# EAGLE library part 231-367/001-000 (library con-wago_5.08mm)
Serie 231, Stiftleiste (für Leiterplatten) Einlötstift gerade 1,2x1,2 mm / Series 231, Male header (for PCBs) Straight solder pin 1.2 x 1.2 mm Polzahl / Pole No.: 7 Rastermaß / Pitch: 5.08 mm Bemessungsspannung / Rated Voltage: 320 V Nennstrom / Nominal Current: 12 A Lötstiftlänge: / Solder Pin Length: 5 mm Farbe / Color: orange / orange Stand: 01.01.2012. Die jeweils aktuellen Daten zu diesem Artikel finden Sie in unserem Produktkatalog, den Sie unter www.wago.com einsehen können. As of: 01/01/2012. Please find the newest data for this article in our product catalogue, which can be viewed under www.wago.com.

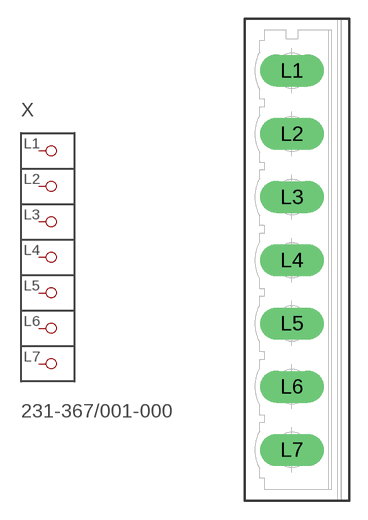
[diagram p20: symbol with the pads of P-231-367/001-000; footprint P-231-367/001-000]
Designator prefix X

## 231-367/001-000  [P-231-367/001-000]
L1  P1
L2  P2
L3  P3
L4  P4
L5  P5
L6  P6
L7  P7

## Footprint P-231-367/001-000 (pad centres in mm)
drill 1.7 long: L1 -0.4,15.2; L2 -0.4,10.12; L3 -0.4,5.04; L4 -0.4,-0.04; L5 -0.4,-5.12; L6 -0.4,-10.2; L7 -0.4,-15.28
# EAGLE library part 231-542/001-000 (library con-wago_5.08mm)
Serie 231, Stiftleiste mit abgewinkelten Einlötstiften / Series 231, Male connector with angled solder pins Polzahl / Pole No.: 12 Rastermaß / Pitch: 5.08 mm Bemessungsspannung / Rated Voltage: 320 V Nennstrom / Nominal Current: 16 A Lötstiftlänge: / Solder Pin Length: 3.8 mm Farbe / Color: orange / orange Stand: 01.01.2012. Die jeweils aktuellen Daten zu diesem Artikel finden Sie in unserem Produktkatalog, den Sie unter www.wago.com einsehen können. As of: 01/01/2012. Please find the newest data for this article in our product catalogue, which can be viewed under www.wago.com.

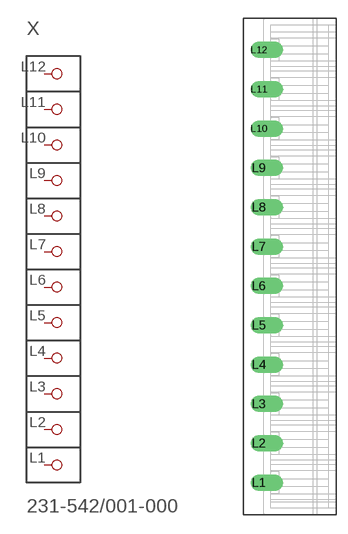
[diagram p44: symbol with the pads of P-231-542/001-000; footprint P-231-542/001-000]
Designator prefix X

## 231-542/001-000  [P-231-542/001-000]
L1  P1
L2  P2
L3  P3
L4  P4
L5  P5
L6  P6
L7  P7
L8  P8
L9  P9
L10  P10
L11  P11
L12  P12

## Footprint P-231-542/001-000 (pad centres in mm)
drill 1.4 offset: L1 -4,-27.9; L2 -4,-22.82; L3 -4,-17.74; L4 -4,-12.66; L5 -4,-7.58; L6 -4,-2.5; L7 -4,2.58; L8 -4,7.66; L9 -4,12.74; L10 -4,17.82; L11 -3.99,22.9; L12 -4,27.98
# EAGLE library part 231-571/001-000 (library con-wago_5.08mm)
Serie 231, Stiftleiste mit abgewinkelten Einlötstiften / Series 231, Male connector with angled solder pins Polzahl / Pole No.: 11 Rastermaß / Pitch: 5.08 mm Bemessungsspannung / Rated Voltage: 320 V Nennstrom / Nominal Current: 16 A Lötstiftlänge: / Solder Pin Length: 3.8 mm Farbe / Color: orange / orange Stand: 01.01.2012. Die jeweils aktuellen Daten zu diesem Artikel finden Sie in unserem Produktkatalog, den Sie unter www.wago.com einsehen können. As of: 01/01/2012. Please find the newest data for this article in our product catalogue, which can be viewed under www.wago.com.

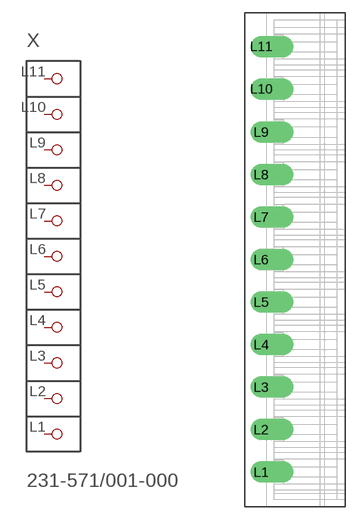
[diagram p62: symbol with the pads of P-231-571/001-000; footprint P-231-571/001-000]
Designator prefix X

## 231-571/001-000  [P-231-571/001-000]
L1  P1
L2  P2
L3  P3
L4  P4
L5  P5
L6  P6
L7  P7
L8  P8
L9  P9
L10  P10
L11  P11

## Footprint P-231-571/001-000 (pad centres in mm)
drill 1.7 offset: L1 -4,-25.36; L2 -4,-20.28; L3 -4,-15.2; L4 -4,-10.12; L5 -4,-5.04; L6 -4,0.04; L7 -4,5.12; L8 -4,10.2; L9 -4,15.28; L10 -3.99,20.36; L11 -4,25.44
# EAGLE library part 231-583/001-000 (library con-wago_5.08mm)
Serie 231, Stiftleiste mit abgewinkelten Einlötstiften / Series 231, Male connector with angled solder pins Polzahl / Pole No.: 23 Rastermaß / Pitch: 5.08 mm Bemessungsspannung / Rated Voltage: 320 V Nennstrom / Nominal Current: 16 A Lötstiftlänge: / Solder Pin Length: 3.8 mm Farbe / Color: orange / orange Stand: 01.01.2012. Die jeweils aktuellen Daten zu diesem Artikel finden Sie in unserem Produktkatalog, den Sie unter www.wago.com einsehen können. As of: 01/01/2012. Please find the newest data for this article in our product catalogue, which can be viewed under www.wago.com.

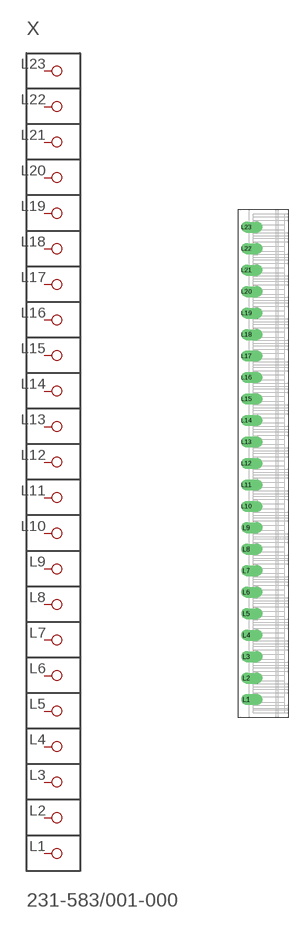
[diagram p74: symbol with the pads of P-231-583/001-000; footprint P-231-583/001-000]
Designator prefix X

## 231-583/001-000  [P-231-583/001-000]
L1  P1
L2  P2
L3  P3
L4  P4
L5  P5
L6  P6
L7  P7
L8  P8
L9  P9
L10  P10
L11  P11
L12  P12
L13  P13
L14  P14
L15  P15
L16  P16
L17  P17
L18  P18
L19  P19
L20  P20
L21  P21
L22  P22
L23  P23

## Footprint P-231-583/001-000 (pad centres in mm)
drill 1.7 offset: L1 -4,-55.84; L2 -4,-50.76; L3 -4,-45.68; L4 -4,-40.6; L5 -4,-35.52; L6 -4,-30.44; L7 -4,-25.36; L8 -4,-20.28; L9 -4,-15.2; L10 -4,-10.12; L11 -4,-5.04; L12 -4,0.04; L13 -4,5.12; L14 -4,10.2; L15 -4,15.28; L16 -4,20.36; L17 -4,25.44; L18 -4,30.52; L19 -4,35.6; L20 -4,40.68; L21 -4,45.76; L22 -3.99,50.84; L23 -4,55.92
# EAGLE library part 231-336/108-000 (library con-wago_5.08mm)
Serie 231, Stiftleiste mit geraden Einlötstiften / Series 231, Male connector with straight solder pins Polzahl / Pole No.: 6 Rastermaß / Pitch: 5.08 mm Bemessungsspannung / Rated Voltage: 320 V Nennstrom / Nominal Current: 12 A Lötstiftlänge: / Solder Pin Length: 5 mm Farbe / Color: orange / orange Stand: 01.01.2012. Die jeweils aktuellen Daten zu diesem Artikel finden Sie in unserem Produktkatalog, den Sie unter www.wago.com einsehen können. As of: 01/01/2012. Please find the newest data for this article in our product catalogue, which can be viewed under www.wago.com.

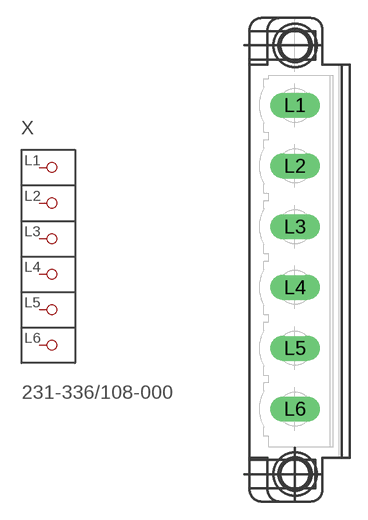
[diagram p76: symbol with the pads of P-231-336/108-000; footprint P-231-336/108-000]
Designator prefix X

## 231-336/108-000  [P-231-336/108-000]
L1  P1
L2  P2
L3  P3
L4  P4
L5  P5
L6  P6

## Footprint P-231-336/108-000 (pad centres in mm)
drill 1.4 long: L1 -0.192,12.925; L2 -0.192,7.845; L3 -0.192,2.765; L4 -0.192,-2.315; L5 -0.192,-7.395; L6 -0.192,-12.475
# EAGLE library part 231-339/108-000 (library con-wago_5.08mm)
Serie 231, Stiftleiste (für Leiterplatten) Einlötstift gerade 1 x 1 mm / Series 231, Male header (for PCBs) Straight solder pin 1 x 1 mm Polzahl / Pole No.: 9 Bemessungsspannung / Rated Voltage: 320 V Nennstrom / Nominal Current: 12 A Lötstiftlänge: / Solder Pin Length: 5 mm Farbe / Color: orange / orange Stand: 01.01.2012. Die jeweils aktuellen Daten zu diesem Artikel finden Sie in unserem Produktkatalog, den Sie unter www.wago.com einsehen können. As of: 01/01/2012. Please find the newest data for this article in our product catalogue, which can be viewed under www.wago.com.

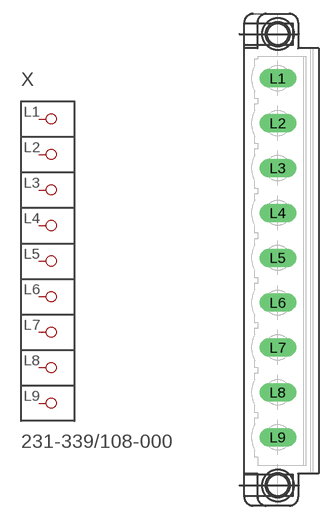
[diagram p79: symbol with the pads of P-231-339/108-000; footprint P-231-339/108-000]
Designator prefix X

## 231-339/108-000  [P-231-339/108-000]
L1  P1
L2  P2
L3  P3
L4  P4
L5  P5
L6  P6
L7  P7
L8  P8
L9  P9

## Footprint P-231-339/108-000 (pad centres in mm)
drill 1.4 long: L1 -0.117,20.545; L2 -0.117,15.465; L3 -0.117,10.385; L4 -0.117,5.305; L5 -0.117,0.225; L6 -0.117,-4.855; L7 -0.117,-9.935; L8 -0.117,-15.015; L9 -0.117,-20.095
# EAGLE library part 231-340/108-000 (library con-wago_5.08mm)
Serie 231, Stiftleiste (für Leiterplatten) Einlötstift gerade 1 x 1 mm / Series 231, Male header (for PCBs) Straight solder pin 1 x 1 mm Polzahl / Pole No.: 10 Bemessungsspannung / Rated Voltage: 320 V Nennstrom / Nominal Current: 12 A Lötstiftlänge: / Solder Pin Length: 5 mm Farbe / Color: orange / orange Stand: 01.01.2012. Die jeweils aktuellen Daten zu diesem Artikel finden Sie in unserem Produktkatalog, den Sie unter www.wago.com einsehen können. As of: 01/01/2012. Please find the newest data for this article in our product catalogue, which can be viewed under www.wago.com.

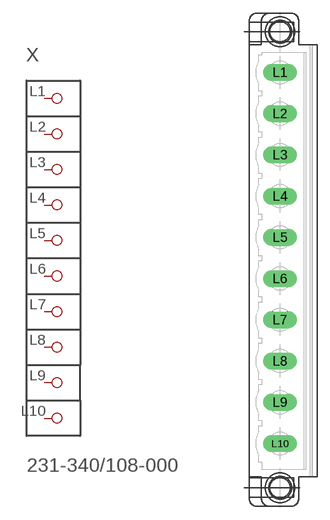
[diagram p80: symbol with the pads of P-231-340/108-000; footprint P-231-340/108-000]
Designator prefix X

## 231-340/108-000  [P-231-340/108-000]
L1  P1
L2  P2
L3  P3
L4  P4
L5  P5
L6  P6
L7  P7
L8  P8
L9  P9
L10  P10

## Footprint P-231-340/108-000 (pad centres in mm)
drill 1.4 long: L1 -0.092,23.085; L2 -0.092,18.005; L3 -0.092,12.925; L4 -0.092,7.845; L5 -0.092,2.765; L6 -0.092,-2.315; L7 -0.092,-7.395; L8 -0.092,-12.475; L9 -0.092,-17.555; L10 -0.092,-22.635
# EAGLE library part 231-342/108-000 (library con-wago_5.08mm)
Serie 231, Stiftleiste (für Leiterplatten) Einlötstift gerade 1 x 1 mm / Series 231, Male header (for PCBs) Straight solder pin 1 x 1 mm Polzahl / Pole No.: 12 Bemessungsspannung / Rated Voltage: 320 V Nennstrom / Nominal Current: 12 A Lötstiftlänge: / Solder Pin Length: 5 mm Farbe / Color: orange / orange Stand: 01.01.2012. Die jeweils aktuellen Daten zu diesem Artikel finden Sie in unserem Produktkatalog, den Sie unter www.wago.com einsehen können. As of: 01/01/2012. Please find the newest data for this article in our product catalogue, which can be viewed under www.wago.com.

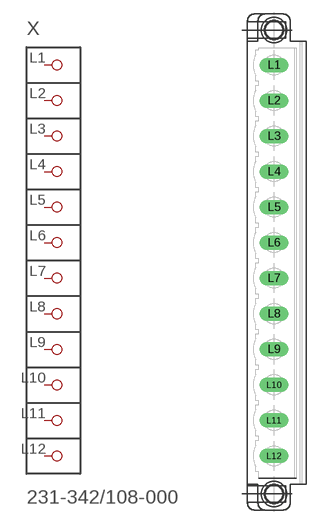
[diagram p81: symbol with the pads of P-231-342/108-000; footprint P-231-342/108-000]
Designator prefix X

## 231-342/108-000  [P-231-342/108-000]
L1  P1
L2  P2
L3  P3
L4  P4
L5  P5
L6  P6
L7  P7
L8  P8
L9  P9
L10  P10
L11  P11
L12  P12

## Footprint P-231-342/108-000 (pad centres in mm)
drill 1.4 long: L1 -0.042,28.165; L2 -0.042,23.085; L3 -0.042,18.005; L4 -0.042,12.925; L5 -0.042,7.845; L6 -0.042,2.765; L7 -0.042,-2.315; L8 -0.042,-7.395; L9 -0.042,-12.475; L10 -0.042,-17.555; L11 -0.042,-22.635; L12 -0.042,-27.715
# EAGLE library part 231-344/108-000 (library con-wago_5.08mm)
Serie 231, Stiftleiste mit geraden Einlötstiften / Series 231, Male connector with straight solder pins Polzahl / Pole No.: 14 Bemessungsspannung / Rated Voltage: 320 V Nennstrom / Nominal Current: 12 A Lötstiftlänge: / Solder Pin Length: 5 mm Farbe / Color: orange / orange Stand: 01.01.2012. Die jeweils aktuellen Daten zu diesem Artikel finden Sie in unserem Produktkatalog, den Sie unter www.wago.com einsehen können. As of: 01/01/2012. Please find the newest data for this article in our product catalogue, which can be viewed under www.wago.com.

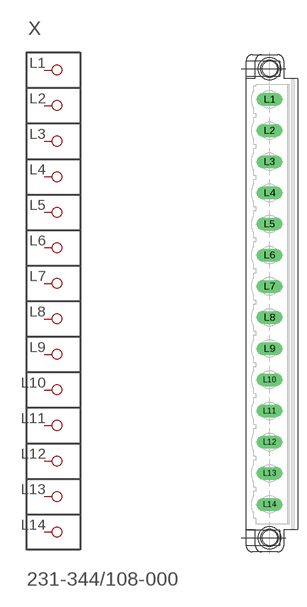
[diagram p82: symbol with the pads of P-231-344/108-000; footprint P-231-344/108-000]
Designator prefix X

## 231-344/108-000  [P-231-344/108-000]
L1  P1
L2  P2
L3  P3
L4  P4
L5  P5
L6  P6
L7  P7
L8  P8
L9  P9
L10  P10
L11  P11
L12  P12
L13  P13
L14  P14

## Footprint P-231-344/108-000 (pad centres in mm)
drill 1.4 long: L1 0.008,33.245; L2 0.008,28.165; L3 0.008,23.085; L4 0.008,18.005; L5 0.008,12.925; L6 0.008,7.845; L7 0.008,2.765; L8 0.008,-2.315; L9 0.008,-7.395; L10 0.008,-12.475; L11 0.008,-17.555; L12 0.008,-22.635; L13 0.008,-27.715; L14 0.008,-32.795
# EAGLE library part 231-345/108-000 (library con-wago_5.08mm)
Serie 231, Stiftleiste mit geraden Einlötstiften / Series 231, Male connector with straight solder pins Polzahl / Pole No.: 15 Rastermaß / Pitch: 5.08 mm Bemessungsspannung / Rated Voltage: 320 V Nennstrom / Nominal Current: 12 A Lötstiftlänge: / Solder Pin Length: 5 mm Farbe / Color: orange / orange Stand: 01.01.2012. Die jeweils aktuellen Daten zu diesem Artikel finden Sie in unserem Produktkatalog, den Sie unter www.wago.com einsehen können. As of: 01/01/2012. Please find the newest data for this article in our product catalogue, which can be viewed under www.wago.com.

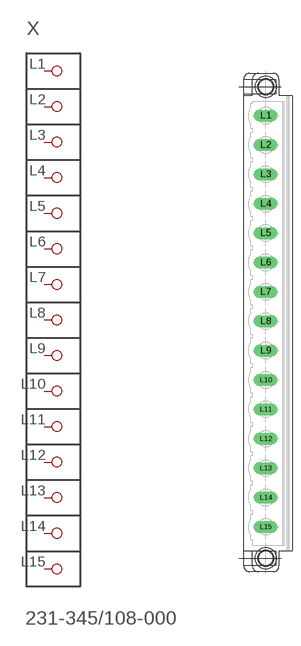
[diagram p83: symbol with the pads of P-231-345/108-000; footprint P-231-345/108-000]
Designator prefix X

## 231-345/108-000  [P-231-345/108-000]
L1  P1
L2  P2
L3  P3
L4  P4
L5  P5
L6  P6
L7  P7
L8  P8
L9  P9
L10  P10
L11  P11
L12  P12
L13  P13
L14  P14
L15  P15

## Footprint P-231-345/108-000 (pad centres in mm)
drill 1.4 long: L1 0.034,35.785; L2 0.034,30.705; L3 0.034,25.625; L4 0.034,20.545; L5 0.034,15.465; L6 0.034,10.385; L7 0.034,5.305; L8 0.034,0.225; L9 0.034,-4.855; L10 0.034,-9.935; L11 0.034,-15.015; L12 0.034,-20.095; L13 0.034,-25.175; L14 0.034,-30.255; L15 0.034,-35.335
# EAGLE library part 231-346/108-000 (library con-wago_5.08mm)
Serie 231, Stiftleiste mit geraden Einlötstiften / Series 231, Male connector with straight solder pins Polzahl / Pole No.: 16 Bemessungsspannung / Rated Voltage: 320 V Nennstrom / Nominal Current: 12 A Lötstiftlänge: / Solder Pin Length: 5 mm Farbe / Color: orange / orange Stand: 01.01.2012. Die jeweils aktuellen Daten zu diesem Artikel finden Sie in unserem Produktkatalog, den Sie unter www.wago.com einsehen können. As of: 01/01/2012. Please find the newest data for this article in our product catalogue, which can be viewed under www.wago.com.

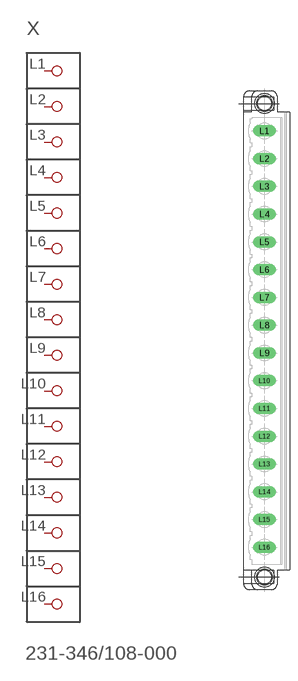
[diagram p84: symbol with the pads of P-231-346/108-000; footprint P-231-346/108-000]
Designator prefix X

## 231-346/108-000  [P-231-346/108-000]
L1  P1
L2  P2
L3  P3
L4  P4
L5  P5
L6  P6
L7  P7
L8  P8
L9  P9
L10  P10
L11  P11
L12  P12
L13  P13
L14  P14
L15  P15
L16  P16

## Footprint P-231-346/108-000 (pad centres in mm)
drill 1.4 long: L1 0.059,38.325; L2 0.059,33.245; L3 0.059,28.165; L4 0.059,23.085; L5 0.059,18.005; L6 0.059,12.925; L7 0.059,7.845; L8 0.059,2.765; L9 0.059,-2.315; L10 0.059,-7.395; L11 0.059,-12.475; L12 0.059,-17.555; L13 0.059,-22.635; L14 0.059,-27.715; L15 0.059,-32.795; L16 0.059,-37.875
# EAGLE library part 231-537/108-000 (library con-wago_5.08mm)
Serie 231, Stiftleiste mit abgewinkelten Einlötstiften / Series 231, Male connector with angled solder pins Polzahl / Pole No.: 7 Bemessungsspannung / Rated Voltage: 320 V Nennstrom / Nominal Current: 12 A Lötstiftlänge: / Solder Pin Length: 3.8 mm Farbe / Color: orange / orange Stand: 01.01.2012. Die jeweils aktuellen Daten zu diesem Artikel finden Sie in unserem Produktkatalog, den Sie unter www.wago.com einsehen können. As of: 01/01/2012. Please find the newest data for this article in our product catalogue, which can be viewed under www.wago.com.

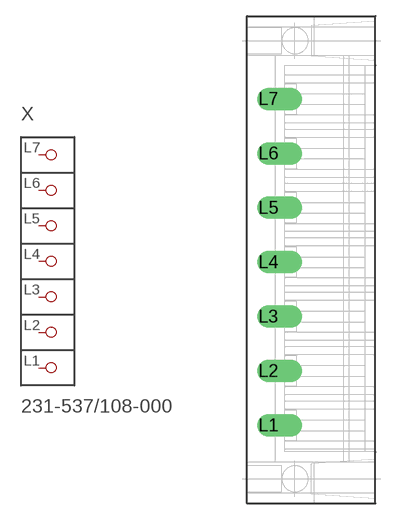
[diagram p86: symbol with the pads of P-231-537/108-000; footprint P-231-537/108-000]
Designator prefix X

## 231-537/108-000  [P-231-537/108-000]
L1  P1
L2  P2
L3  P3
L4  P4
L5  P5
L6  P6
L7  P7

## Footprint P-231-537/108-000 (pad centres in mm)
drill 1.4 offset: L1 -4,-15.465; L2 -4,-10.385; L3 -4,-5.305; L4 -4,-0.225; L5 -4,4.855; L6 -4,9.935; L7 -4,15.025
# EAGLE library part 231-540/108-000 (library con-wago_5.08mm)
Serie 231, Stiftleiste mit abgewinkelten Einlötstiften / Series 231, Male connector with angled solder pins Polzahl / Pole No.: 10 Bemessungsspannung / Rated Voltage: 320 V Nennstrom / Nominal Current: 12 A Lötstiftlänge: / Solder Pin Length: 3.8 mm Farbe / Color: orange / orange Stand: 01.01.2012. Die jeweils aktuellen Daten zu diesem Artikel finden Sie in unserem Produktkatalog, den Sie unter www.wago.com einsehen können. As of: 01/01/2012. Please find the newest data for this article in our product catalogue, which can be viewed under www.wago.com.

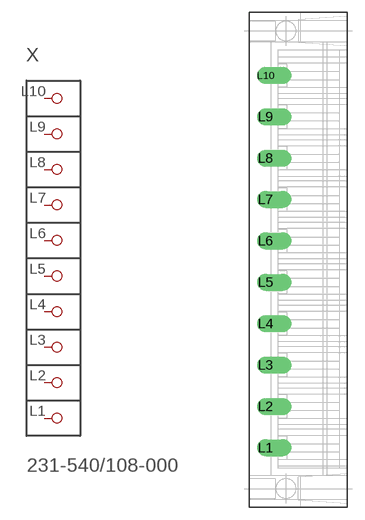
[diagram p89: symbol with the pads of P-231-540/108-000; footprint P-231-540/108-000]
Designator prefix X

## 231-540/108-000  [P-231-540/108-000]
L1  P1
L2  P2
L3  P3
L4  P4
L5  P5
L6  P6
L7  P7
L8  P8
L9  P9
L10  P10

## Footprint P-231-540/108-000 (pad centres in mm)
drill 1.4 offset: L1 -4,-23.085; L2 -4,-18.005; L3 -4,-12.925; L4 -4,-7.845; L5 -4,-2.765; L6 -4,2.315; L7 -4,7.395; L8 -4,12.475; L9 -4,17.555; L10 -4,22.645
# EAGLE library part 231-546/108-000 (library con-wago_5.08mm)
Serie 231, Stiftleiste (für Leiterplatten) Einlötstift abgewinkelt 1 x 1 mm / Series 231, Male header (for PCBs) Angled solder pin 1 x 1 mm Polzahl / Pole No.: 16 Bemessungsspannung / Rated Voltage: 320 V Nennstrom / Nominal Current: 12 A Lötstiftlänge: / Solder Pin Length: 3.8 mm Farbe / Color: orange / orange Stand: 01.01.2012. Die jeweils aktuellen Daten zu diesem Artikel finden Sie in unserem Produktkatalog, den Sie unter www.wago.com einsehen können. As of: 01/01/2012. Please find the newest data for this article in our product catalogue, which can be viewed under www.wago.com.

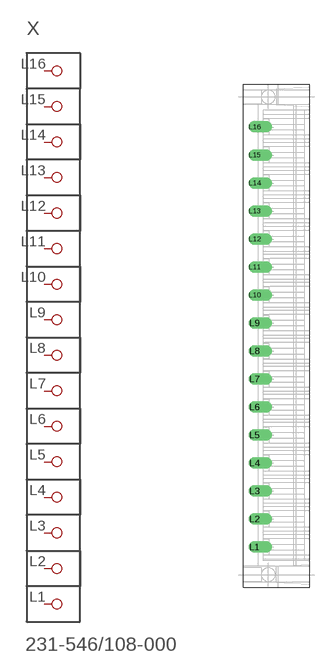
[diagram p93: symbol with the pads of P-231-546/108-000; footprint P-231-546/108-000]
Designator prefix X

## 231-546/108-000  [P-231-546/108-000]
L1  P1
L2  P2
L3  P3
L4  P4
L5  P5
L6  P6
L7  P7
L8  P8
L9  P9
L10  P10
L11  P11
L12  P12
L13  P13
L14  P14
L15  P15
L16  P16

## Footprint P-231-546/108-000 (pad centres in mm)
drill 1.4 offset: L1 -4,-38.325; L2 -4,-33.245; L3 -4,-28.165; L4 -4,-23.085; L5 -4,-18.005; L6 -4,-12.925; L7 -4,-7.845; L8 -4,-2.765; L9 -4,2.315; L10 -4,7.395; L11 -4,12.475; L12 -4,17.555; L13 -4,22.635; L14 -4,27.715; L15 -4,32.795; L16 -4,37.885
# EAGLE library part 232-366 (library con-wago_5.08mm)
Serie 232, Aufstock-Stiftleisten mit abgewinkelten Einlötstiften / Series 232, Male headers for double-deck assembly with angled solder pins Polzahl / Pole No.: 6 Rastermaß / Pitch: 5.08 mm Bemessungsspannung / Rated Voltage: 320 V Nennstrom / Nominal Current: 12 A Lötstiftlänge: / Solder Pin Length: 5 mm Farbe / Color: orange / orange Stand: 01.01.2012. Die jeweils aktuellen Daten zu diesem Artikel finden Sie in unserem Produktkatalog, den Sie unter www.wago.com einsehen können. As of: 01/01/2012. Please find the newest data for this article in our product catalogue, which can be viewed under www.wago.com.

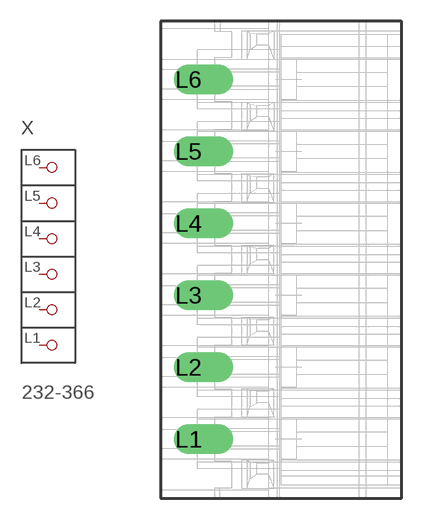
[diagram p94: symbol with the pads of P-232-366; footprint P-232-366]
Designator prefix X

## 232-366  [P-232-366]
L1  P1
L2  P2
L3  P3
L4  P4
L5  P5
L6  P6

## Footprint P-232-366 (pad centres in mm)
drill 1.4 offset: L1 -6.52,-12.66; L2 -6.52,-7.58; L3 -6.52,-2.5; L4 -6.52,2.58; L5 -6.52,7.66; L6 -6.52,12.74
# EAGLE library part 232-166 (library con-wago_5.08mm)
Serie 232, Federleiste mit geraden Einlötstiften / Series 232, Female connector with straight solder pins Polzahl / Pole No.: 6 Rastermaß / Pitch: 5.08 mm Bemessungsspannung / Rated Voltage: 160 V Nennstrom / Nominal Current: 6 A Lötstiftlänge: / Solder Pin Length: 5 mm Farbe / Color: orange / orange Stand: 01.01.2012. Die jeweils aktuellen Daten zu diesem Artikel finden Sie in unserem Produktkatalog, den Sie unter www.wago.com einsehen können. As of: 01/01/2012. Please find the newest data for this article in our product catalogue, which can be viewed under www.wago.com.

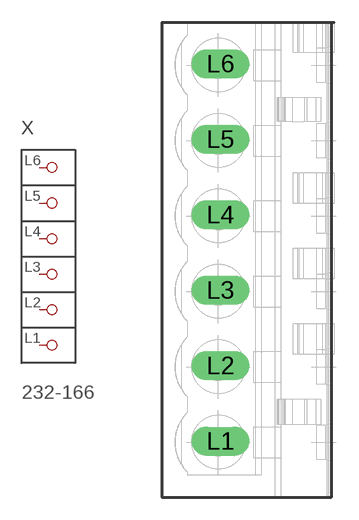
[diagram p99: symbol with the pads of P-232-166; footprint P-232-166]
Designator prefix X

## 232-166  [P-232-166]
L1  P1
L2  P2
L3  P3
L4  P4
L5  P5
L6  P6

## Footprint P-232-166 (pad centres in mm)
drill 1.3 long: L1 -1.926,-12.21; L2 -1.926,-7.13; L3 -1.926,-2.05; L4 -1.926,3.03; L5 -1.926,8.11; L6 -1.926,13.19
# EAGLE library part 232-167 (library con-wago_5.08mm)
Serie 232, Federleiste mit geraden Einlötstiften / Series 232, Female connector with straight solder pins Polzahl / Pole No.: 7 Rastermaß / Pitch: 5.08 mm Bemessungsspannung / Rated Voltage: 160 V Nennstrom / Nominal Current: 6 A Lötstiftlänge: / Solder Pin Length: 5 mm Farbe / Color: orange / orange Stand: 01.01.2012. Die jeweils aktuellen Daten zu diesem Artikel finden Sie in unserem Produktkatalog, den Sie unter www.wago.com einsehen können. As of: 01/01/2012. Please find the newest data for this article in our product catalogue, which can be viewed under www.wago.com.

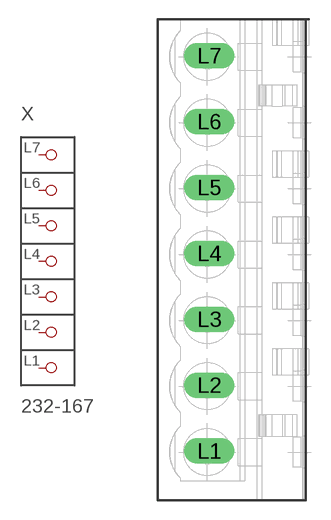
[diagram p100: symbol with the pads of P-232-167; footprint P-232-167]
Designator prefix X

## 232-167  [P-232-167]
L1  P1
L2  P2
L3  P3
L4  P4
L5  P5
L6  P6
L7  P7

## Footprint P-232-167 (pad centres in mm)
drill 1.3 long: L1 -1.95,-14.75; L2 -1.95,-9.67; L3 -1.95,-4.59; L4 -1.95,0.49; L5 -1.95,5.57; L6 -1.95,10.65; L7 -1.95,15.73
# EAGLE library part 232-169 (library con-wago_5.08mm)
Serie 232, Federleiste mit geraden Einlötstiften / Series 232, Female connector with straight solder pins Polzahl / Pole No.: 9 Rastermaß / Pitch: 5.08 mm Bemessungsspannung / Rated Voltage: 160 V Nennstrom / Nominal Current: 6 A Lötstiftlänge: / Solder Pin Length: 5 mm Farbe / Color: orange / orange Stand: 01.01.2012. Die jeweils aktuellen Daten zu diesem Artikel finden Sie in unserem Produktkatalog, den Sie unter www.wago.com einsehen können. As of: 01/01/2012. Please find the newest data for this article in our product catalogue, which can be viewed under www.wago.com.

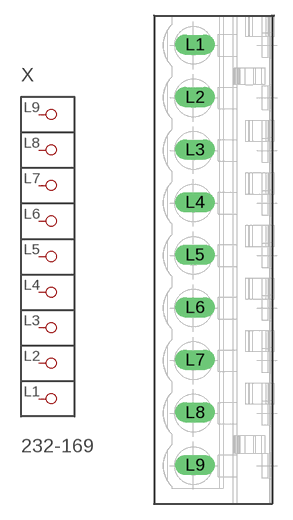
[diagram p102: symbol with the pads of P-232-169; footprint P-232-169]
Designator prefix X

## 232-169  [P-232-169]
L1  P1
L2  P2
L3  P3
L4  P4
L5  P5
L6  P6
L7  P7
L8  P8
L9  P9

## Footprint P-232-169 (pad centres in mm)
drill 1.3 long: L1 -1.998,20.81; L2 -1.998,15.73; L3 -1.998,10.65; L4 -1.998,5.57; L5 -1.998,0.49; L6 -1.998,-4.59; L7 -1.998,-9.67; L8 -1.998,-14.75; L9 -1.998,-19.83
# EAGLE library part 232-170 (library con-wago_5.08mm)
Serie 232, Federleiste mit geraden Einlötstiften / Series 232, Female connector with straight solder pins Polzahl / Pole No.: 10 Rastermaß / Pitch: 5.08 mm Bemessungsspannung / Rated Voltage: 160 V Nennstrom / Nominal Current: 6 A Lötstiftlänge: / Solder Pin Length: 5 mm Farbe / Color: orange / orange Stand: 01.01.2012. Die jeweils aktuellen Daten zu diesem Artikel finden Sie in unserem Produktkatalog, den Sie unter www.wago.com einsehen können. As of: 01/01/2012. Please find the newest data for this article in our product catalogue, which can be viewed under www.wago.com.

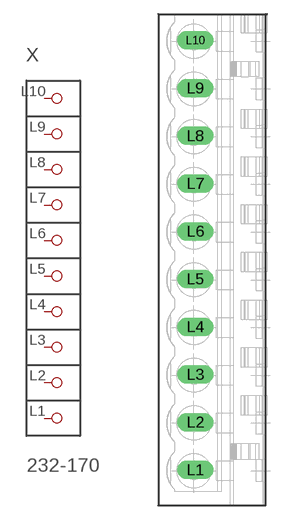
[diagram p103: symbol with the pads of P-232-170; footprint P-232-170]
Designator prefix X

## 232-170  [P-232-170]
L1  P1
L2  P2
L3  P3
L4  P4
L5  P5
L6  P6
L7  P7
L8  P8
L9  P9
L10  P10

## Footprint P-232-170 (pad centres in mm)
drill 1.3 long: L1 -2.023,-22.37; L2 -2.023,-17.29; L3 -2.023,-12.21; L4 -2.023,-7.13; L5 -2.023,-2.05; L6 -2.023,3.03; L7 -2.023,8.11; L8 -2.023,13.19; L9 -2.023,18.27; L10 -2.023,23.35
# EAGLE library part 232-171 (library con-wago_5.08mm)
Serie 232, Federleiste mit geraden Einlötstiften / Series 232, Female connector with straight solder pins Polzahl / Pole No.: 11 Rastermaß / Pitch: 5.08 mm Bemessungsspannung / Rated Voltage: 160 V Nennstrom / Nominal Current: 6 A Lötstiftlänge: / Solder Pin Length: 5 mm Farbe / Color: orange / orange Stand: 01.01.2012. Die jeweils aktuellen Daten zu diesem Artikel finden Sie in unserem Produktkatalog, den Sie unter www.wago.com einsehen können. As of: 01/01/2012. Please find the newest data for this article in our product catalogue, which can be viewed under www.wago.com.

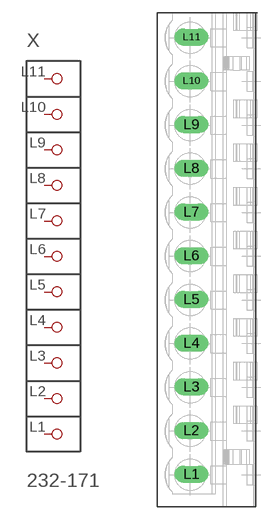
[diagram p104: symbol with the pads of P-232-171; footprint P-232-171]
Designator prefix X

## 232-171  [P-232-171]
L1  P1
L2  P2
L3  P3
L4  P4
L5  P5
L6  P6
L7  P7
L8  P8
L9  P9
L10  P10
L11  P11

## Footprint P-232-171 (pad centres in mm)
drill 1.3 long: L1 -2.048,-24.91; L2 -2.048,-19.83; L3 -2.048,-14.75; L4 -2.048,-9.67; L5 -2.048,-4.59; L6 -2.048,0.49; L7 -2.048,5.57; L8 -2.048,10.65; L9 -2.048,15.73; L10 -2.048,20.81; L11 -2.048,25.89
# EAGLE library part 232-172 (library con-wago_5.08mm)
Serie 232, Federleiste mit geraden Einlötstiften / Series 232, Female connector with straight solder pins Polzahl / Pole No.: 12 Rastermaß / Pitch: 5.08 mm Bemessungsspannung / Rated Voltage: 160 V Nennstrom / Nominal Current: 6 A Lötstiftlänge: / Solder Pin Length: 5 mm Farbe / Color: orange / orange Stand: 01.01.2012. Die jeweils aktuellen Daten zu diesem Artikel finden Sie in unserem Produktkatalog, den Sie unter www.wago.com einsehen können. As of: 01/01/2012. Please find the newest data for this article in our product catalogue, which can be viewed under www.wago.com.

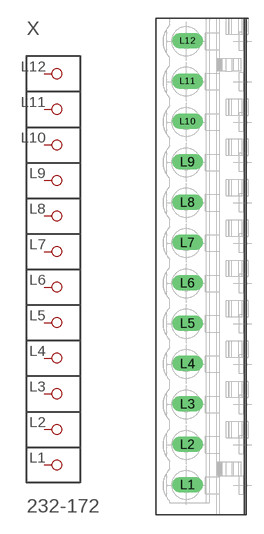
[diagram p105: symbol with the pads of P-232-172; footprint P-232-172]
Designator prefix X

## 232-172  [P-232-172]
L1  P1
L2  P2
L3  P3
L4  P4
L5  P5
L6  P6
L7  P7
L8  P8
L9  P9
L10  P10
L11  P11
L12  P12

## Footprint P-232-172 (pad centres in mm)
drill 1.3 long: L1 -2.072,-27.45; L2 -2.072,-22.37; L3 -2.072,-17.29; L4 -2.072,-12.21; L5 -2.072,-7.13; L6 -2.072,-2.05; L7 -2.072,3.03; L8 -2.072,8.11; L9 -2.072,13.19; L10 -2.072,18.27; L11 -2.072,23.35; L12 -2.072,28.43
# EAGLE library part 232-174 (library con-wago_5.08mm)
Serie 232, Federleiste mit geraden Einlötstiften / Series 232, Female connector with straight solder pins Polzahl / Pole No.: 14 Rastermaß / Pitch: 5.08 mm Bemessungsspannung / Rated Voltage: 160 V Nennstrom / Nominal Current: 6 A Lötstiftlänge: / Solder Pin Length: 5 mm Farbe / Color: orange / orange Stand: 01.01.2012. Die jeweils aktuellen Daten zu diesem Artikel finden Sie in unserem Produktkatalog, den Sie unter www.wago.com einsehen können. As of: 01/01/2012. Please find the newest data for this article in our product catalogue, which can be viewed under www.wago.com.

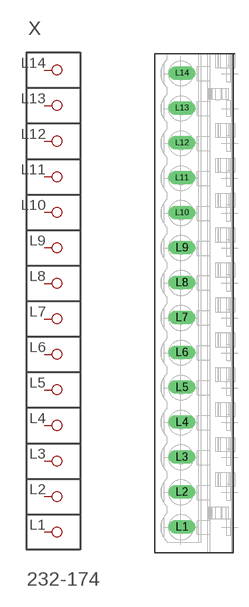
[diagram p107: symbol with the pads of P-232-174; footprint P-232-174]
Designator prefix X

## 232-174  [P-232-174]
L1  P1
L2  P2
L3  P3
L4  P4
L5  P5
L6  P6
L7  P7
L8  P8
L9  P9
L10  P10
L11  P11
L12  P12
L13  P13
L14  P14

## Footprint P-232-174 (pad centres in mm)
drill 1.3 long: L1 -2.123,-32.53; L2 -2.123,-27.45; L3 -2.123,-22.37; L4 -2.123,-17.29; L5 -2.123,-12.21; L6 -2.123,-7.13; L7 -2.123,-2.05; L8 -2.123,3.03; L9 -2.123,8.11; L10 -2.123,13.19; L11 -2.123,18.27; L12 -2.123,23.35; L13 -2.123,28.43; L14 -2.123,33.51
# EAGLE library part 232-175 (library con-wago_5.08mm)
Serie 232, Federleiste mit geraden Einlötstiften / Series 232, Female connector with straight solder pins Polzahl / Pole No.: 15 Rastermaß / Pitch: 5.08 mm Bemessungsspannung / Rated Voltage: 160 V Nennstrom / Nominal Current: 6 A Lötstiftlänge: / Solder Pin Length: 5 mm Farbe / Color: orange / orange Stand: 01.01.2012. Die jeweils aktuellen Daten zu diesem Artikel finden Sie in unserem Produktkatalog, den Sie unter www.wago.com einsehen können. As of: 01/01/2012. Please find the newest data for this article in our product catalogue, which can be viewed under www.wago.com.

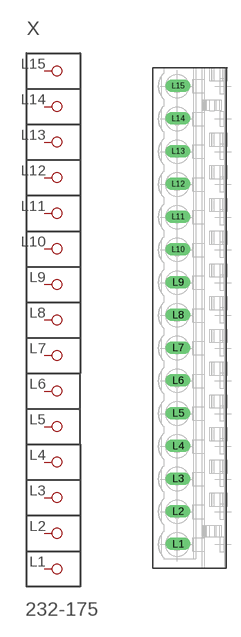
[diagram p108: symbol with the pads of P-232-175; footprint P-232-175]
Designator prefix X

## 232-175  [P-232-175]
L1  P1
L2  P2
L3  P3
L4  P4
L5  P5
L6  P6
L7  P7
L8  P8
L9  P9
L10  P10
L11  P11
L12  P12
L13  P13
L14  P14
L15  P15

## Footprint P-232-175 (pad centres in mm)
drill 1.3 long: L1 -2.147,-35.07; L2 -2.147,-29.99; L3 -2.147,-24.91; L4 -2.147,-19.83; L5 -2.147,-14.75; L6 -2.147,-9.67; L7 -2.147,-4.59; L8 -2.147,0.49; L9 -2.147,5.57; L10 -2.147,10.65; L11 -2.147,15.73; L12 -2.147,20.81; L13 -2.147,25.89; L14 -2.147,30.97; L15 -2.147,36.05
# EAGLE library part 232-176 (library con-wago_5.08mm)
Serie 232, Federleiste mit geraden Einlötstiften / Series 232, Female connector with straight solder pins Polzahl / Pole No.: 16 Rastermaß / Pitch: 5.08 mm Bemessungsspannung / Rated Voltage: 160 V Nennstrom / Nominal Current: 6 A Lötstiftlänge: / Solder Pin Length: 5 mm Farbe / Color: orange / orange Stand: 01.01.2012. Die jeweils aktuellen Daten zu diesem Artikel finden Sie in unserem Produktkatalog, den Sie unter www.wago.com einsehen können. As of: 01/01/2012. Please find the newest data for this article in our product catalogue, which can be viewed under www.wago.com.

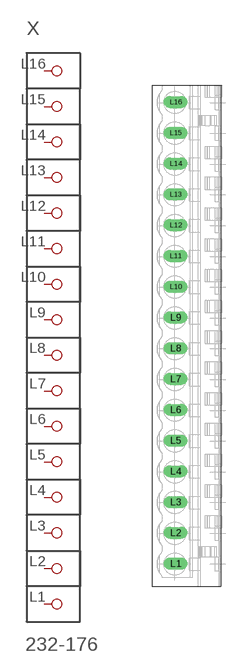
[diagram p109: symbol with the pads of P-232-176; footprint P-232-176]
Designator prefix X

## 232-176  [P-232-176]
L1  P1
L2  P2
L3  P3
L4  P4
L5  P5
L6  P6
L7  P7
L8  P8
L9  P9
L10  P10
L11  P11
L12  P12
L13  P13
L14  P14
L15  P15
L16  P16

## Footprint P-232-176 (pad centres in mm)
drill 1.3 long: L1 -2.173,-37.61; L2 -2.173,-32.53; L3 -2.173,-27.45; L4 -2.173,-22.37; L5 -2.173,-17.29; L6 -2.173,-12.21; L7 -2.173,-7.13; L8 -2.173,-2.05; L9 -2.173,3.03; L10 -2.173,8.11; L11 -2.173,13.19; L12 -2.173,18.27; L13 -2.173,23.35; L14 -2.173,28.43; L15 -2.173,33.51; L16 -2.173,38.59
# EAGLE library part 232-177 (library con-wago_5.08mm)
Serie 232, Federleiste mit geraden Einlötstiften / Series 232, Female connector with straight solder pins Polzahl / Pole No.: 17 Rastermaß / Pitch: 5.08 mm Bemessungsspannung / Rated Voltage: 160 V Nennstrom / Nominal Current: 6 A Lötstiftlänge: / Solder Pin Length: 5 mm Farbe / Color: orange / orange Stand: 01.01.2012. Die jeweils aktuellen Daten zu diesem Artikel finden Sie in unserem Produktkatalog, den Sie unter www.wago.com einsehen können. As of: 01/01/2012. Please find the newest data for this article in our product catalogue, which can be viewed under www.wago.com.

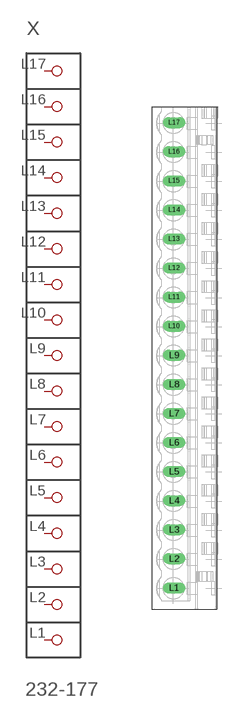
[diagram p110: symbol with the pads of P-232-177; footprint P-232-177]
Designator prefix X

## 232-177  [P-232-177]
L1  P1
L2  P2
L3  P3
L4  P4
L5  P5
L6  P6
L7  P7
L8  P8
L9  P9
L10  P10
L11  P11
L12  P12
L13  P13
L14  P14
L15  P15
L16  P16
L17  P17

## Footprint P-232-177 (pad centres in mm)
drill 1.3 long: L1 -2.198,-40.15; L2 -2.198,-35.07; L3 -2.198,-29.99; L4 -2.198,-24.91; L5 -2.198,-19.83; L6 -2.198,-14.75; L7 -2.198,-9.67; L8 -2.198,-4.59; L9 -2.198,0.49; L10 -2.198,5.57; L11 -2.198,10.65; L12 -2.198,15.73; L13 -2.198,20.81; L14 -2.198,25.89; L15 -2.198,30.97; L16 -2.198,36.05; L17 -2.198,41.13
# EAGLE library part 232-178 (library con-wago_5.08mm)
Serie 232, Federleiste mit geraden Einlötstiften / Series 232, Female connector with straight solder pins Polzahl / Pole No.: 18 Rastermaß / Pitch: 5.08 mm Bemessungsspannung / Rated Voltage: 160 V Nennstrom / Nominal Current: 6 A Lötstiftlänge: / Solder Pin Length: 5 mm Farbe / Color: orange / orange Stand: 01.01.2012. Die jeweils aktuellen Daten zu diesem Artikel finden Sie in unserem Produktkatalog, den Sie unter www.wago.com einsehen können. As of: 01/01/2012. Please find the newest data for this article in our product catalogue, which can be viewed under www.wago.com.

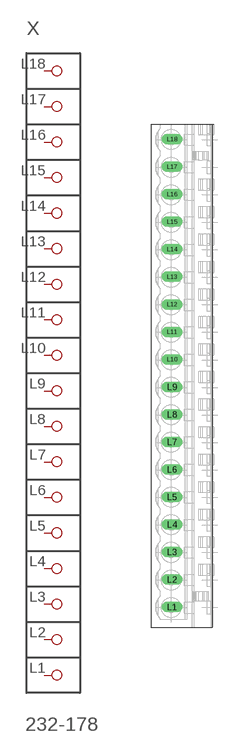
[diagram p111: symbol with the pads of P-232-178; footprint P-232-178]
Designator prefix X

## 232-178  [P-232-178]
L1  P1
L2  P2
L3  P3
L4  P4
L5  P5
L6  P6
L7  P7
L8  P8
L9  P9
L10  P10
L11  P11
L12  P12
L13  P13
L14  P14
L15  P15
L16  P16
L17  P17
L18  P18

## Footprint P-232-178 (pad centres in mm)
drill 1.3 long: L1 -2.223,-42.69; L2 -2.223,-37.61; L3 -2.223,-32.53; L4 -2.223,-27.45; L5 -2.223,-22.37; L6 -2.223,-17.29; L7 -2.223,-12.21; L8 -2.223,-7.13; L9 -2.223,-2.05; L10 -2.223,3.03; L11 -2.223,8.11; L12 -2.223,13.19; L13 -2.223,18.27; L14 -2.223,23.35; L15 -2.223,28.43; L16 -2.223,33.51; L17 -2.223,38.59; L18 -2.223,43.67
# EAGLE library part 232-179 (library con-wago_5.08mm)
Serie 232, Federleiste mit geraden Einlötstiften / Series 232, Female connector with straight solder pins Polzahl / Pole No.: 19 Rastermaß / Pitch: 5.08 mm Bemessungsspannung / Rated Voltage: 160 V Nennstrom / Nominal Current: 6 A Lötstiftlänge: / Solder Pin Length: 5 mm Farbe / Color: orange / orange Stand: 01.01.2012. Die jeweils aktuellen Daten zu diesem Artikel finden Sie in unserem Produktkatalog, den Sie unter www.wago.com einsehen können. As of: 01/01/2012. Please find the newest data for this article in our product catalogue, which can be viewed under www.wago.com.

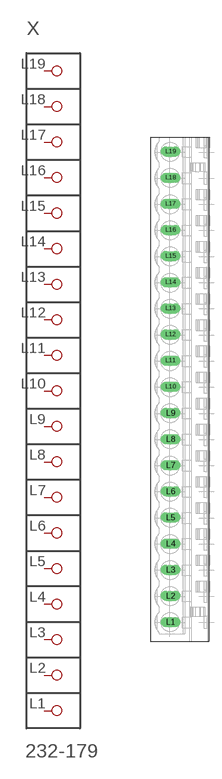
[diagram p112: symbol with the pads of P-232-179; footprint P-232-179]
Designator prefix X

## 232-179  [P-232-179]
L1  P1
L2  P2
L3  P3
L4  P4
L5  P5
L6  P6
L7  P7
L8  P8
L9  P9
L10  P10
L11  P11
L12  P12
L13  P13
L14  P14
L15  P15
L16  P16
L17  P17
L18  P18
L19  P19

## Footprint P-232-179 (pad centres in mm)
drill 1.3 long: L1 -2.248,-45.23; L2 -2.248,-40.15; L3 -2.248,-35.07; L4 -2.248,-29.99; L5 -2.248,-24.91; L6 -2.248,-19.83; L7 -2.248,-14.75; L8 -2.248,-9.67; L9 -2.248,-4.59; L10 -2.248,0.49; L11 -2.248,5.57; L12 -2.248,10.65; L13 -2.248,15.73; L14 -2.248,20.81; L15 -2.248,25.89; L16 -2.248,30.97; L17 -2.248,36.05; L18 -2.248,41.13; L19 -2.248,46.21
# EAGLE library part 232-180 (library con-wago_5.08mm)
Serie 232, Federleiste mit geraden Einlötstiften / Series 232, Female connector with straight solder pins Polzahl / Pole No.: 20 Rastermaß / Pitch: 5.08 mm Bemessungsspannung / Rated Voltage: 160 V Nennstrom / Nominal Current: 6 A Lötstiftlänge: / Solder Pin Length: 5 mm Farbe / Color: orange / orange Stand: 01.01.2012. Die jeweils aktuellen Daten zu diesem Artikel finden Sie in unserem Produktkatalog, den Sie unter www.wago.com einsehen können. As of: 01/01/2012. Please find the newest data for this article in our product catalogue, which can be viewed under www.wago.com.

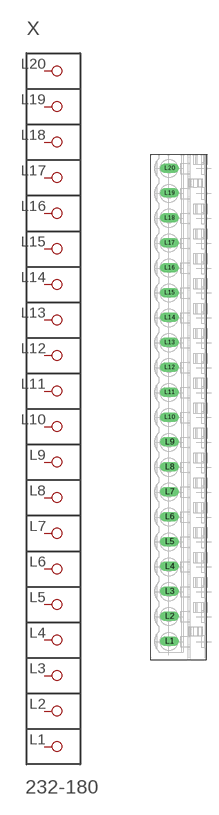
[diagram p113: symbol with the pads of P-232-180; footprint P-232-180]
Designator prefix X

## 232-180  [P-232-180]
L1  P1
L2  P2
L3  P3
L4  P4
L5  P5
L6  P6
L7  P7
L8  P8
L9  P9
L10  P10
L11  P11
L12  P12
L13  P13
L14  P14
L15  P15
L16  P16
L17  P17
L18  P18
L19  P19
L20  P20

## Footprint P-232-180 (pad centres in mm)
drill 1.3 long: L1 -2.273,-47.77; L2 -2.273,-42.69; L3 -2.273,-37.61; L4 -2.273,-32.53; L5 -2.273,-27.45; L6 -2.273,-22.37; L7 -2.273,-17.29; L8 -2.273,-12.21; L9 -2.273,-7.13; L10 -2.273,-2.05; L11 -2.273,3.03; L12 -2.273,8.11; L13 -2.273,13.19; L14 -2.273,18.27; L15 -2.273,23.35; L16 -2.273,28.43; L17 -2.273,33.51; L18 -2.273,38.59; L19 -2.273,43.67; L20 -2.273,48.75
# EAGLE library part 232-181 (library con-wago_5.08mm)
Serie 232, Federleiste mit geraden Einlötstiften / Series 232, Female connector with straight solder pins Polzahl / Pole No.: 21 Rastermaß / Pitch: 5.08 mm Bemessungsspannung / Rated Voltage: 160 V Nennstrom / Nominal Current: 6 A Lötstiftlänge: / Solder Pin Length: 5 mm Farbe / Color: orange / orange Stand: 01.01.2012. Die jeweils aktuellen Daten zu diesem Artikel finden Sie in unserem Produktkatalog, den Sie unter www.wago.com einsehen können. As of: 01/01/2012. Please find the newest data for this article in our product catalogue, which can be viewed under www.wago.com.

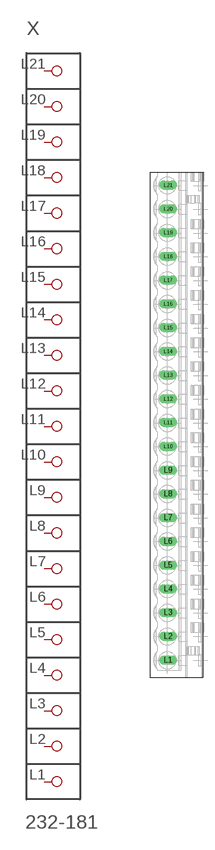
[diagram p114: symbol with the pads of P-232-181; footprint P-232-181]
Designator prefix X

## 232-181  [P-232-181]
L1  P1
L2  P2
L3  P3
L4  P4
L5  P5
L6  P6
L7  P7
L8  P8
L9  P9
L10  P10
L11  P11
L12  P12
L13  P13
L14  P14
L15  P15
L16  P16
L17  P17
L18  P18
L19  P19
L20  P20
L21  P21

## Footprint P-232-181 (pad centres in mm)
drill 1.3 long: L1 -2.299,-50.319; L2 -2.299,-45.239; L3 -2.299,-40.159; L4 -2.299,-35.079; L5 -2.299,-29.999; L6 -2.299,-24.919; L7 -2.299,-19.839; L8 -2.299,-14.759; L9 -2.299,-9.679; L10 -2.299,-4.599; L11 -2.299,0.481; L12 -2.299,5.561; L13 -2.299,10.641; L14 -2.299,15.721; L15 -2.299,20.801; L16 -2.299,25.881; L17 -2.299,30.961; L18 -2.299,36.041; L19 -2.299,41.121; L20 -2.299,46.201; L21 -2.299,51.281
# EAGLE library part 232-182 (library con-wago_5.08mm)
Serie 232, Federleiste mit geraden Einlötstiften / Series 232, Female connector with straight solder pins Polzahl / Pole No.: 22 Rastermaß / Pitch: 5.08 mm Bemessungsspannung / Rated Voltage: 160 V Nennstrom / Nominal Current: 6 A Lötstiftlänge: / Solder Pin Length: 5 mm Farbe / Color: orange / orange Stand: 01.01.2012. Die jeweils aktuellen Daten zu diesem Artikel finden Sie in unserem Produktkatalog, den Sie unter www.wago.com einsehen können. As of: 01/01/2012. Please find the newest data for this article in our product catalogue, which can be viewed under www.wago.com.

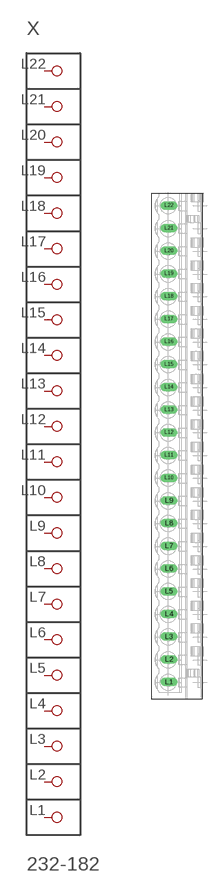
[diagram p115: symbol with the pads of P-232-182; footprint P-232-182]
Designator prefix X

## 232-182  [P-232-182]
L1  P1
L2  P2
L3  P3
L4  P4
L5  P5
L6  P6
L7  P7
L8  P8
L9  P9
L10  P10
L11  P11
L12  P12
L13  P13
L14  P14
L15  P15
L16  P16
L17  P17
L18  P18
L19  P19
L20  P20
L21  P21
L22  P22

## Footprint P-232-182 (pad centres in mm)
drill 1.3 long: L1 -2.324,-52.884; L2 -2.324,-47.804; L3 -2.324,-42.724; L4 -2.324,-37.644; L5 -2.324,-32.564; L6 -2.324,-27.484; L7 -2.324,-22.404; L8 -2.324,-17.324; L9 -2.324,-12.244; L10 -2.324,-7.164; L11 -2.324,-2.084; L12 -2.324,2.996; L13 -2.324,8.076; L14 -2.324,13.156; L15 -2.324,18.236; L16 -2.324,23.316; L17 -2.324,28.396; L18 -2.324,33.476; L19 -2.324,38.556; L20 -2.324,43.636; L21 -2.324,48.716; L22 -2.324,53.796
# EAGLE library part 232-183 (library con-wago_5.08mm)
Serie 232, Federleiste mit geraden Einlötstiften / Series 232, Female connector with straight solder pins Polzahl / Pole No.: 23 Rastermaß / Pitch: 5.08 mm Bemessungsspannung / Rated Voltage: 160 V Nennstrom / Nominal Current: 6 A Lötstiftlänge: / Solder Pin Length: 5 mm Farbe / Color: orange / orange Stand: 01.01.2012. Die jeweils aktuellen Daten zu diesem Artikel finden Sie in unserem Produktkatalog, den Sie unter www.wago.com einsehen können. As of: 01/01/2012. Please find the newest data for this article in our product catalogue, which can be viewed under www.wago.com.

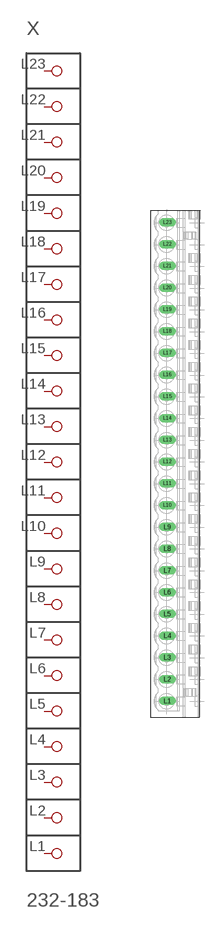
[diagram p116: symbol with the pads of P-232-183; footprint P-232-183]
Designator prefix X

## 232-183  [P-232-183]
L1  P1
L2  P2
L3  P3
L4  P4
L5  P5
L6  P6
L7  P7
L8  P8
L9  P9
L10  P10
L11  P11
L12  P12
L13  P13
L14  P14
L15  P15
L16  P16
L17  P17
L18  P18
L19  P19
L20  P20
L21  P21
L22  P22
L23  P23

## Footprint P-232-183 (pad centres in mm)
drill 1.3 long: L1 -2.349,-55.449; L2 -2.349,-50.369; L3 -2.349,-45.289; L4 -2.349,-40.209; L5 -2.349,-35.129; L6 -2.349,-30.049; L7 -2.349,-24.969; L8 -2.349,-19.889; L9 -2.349,-14.809; L10 -2.349,-9.729; L11 -2.349,-4.649; L12 -2.349,0.431; L13 -2.349,5.511; L14 -2.349,10.591; L15 -2.349,15.671; L16 -2.349,20.751; L17 -2.349,25.831; L18 -2.349,30.911; L19 -2.349,35.991; L20 -2.349,41.071; L21 -2.349,46.151; L22 -2.349,51.231; L23 -2.349,56.311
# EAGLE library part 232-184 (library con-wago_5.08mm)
Serie 232, Federleiste mit geraden Einlötstiften / Series 232, Female connector with straight solder pins Polzahl / Pole No.: 24 Rastermaß / Pitch: 5.08 mm Bemessungsspannung / Rated Voltage: 160 V Nennstrom / Nominal Current: 6 A Lötstiftlänge: / Solder Pin Length: 5 mm Farbe / Color: orange / orange Stand: 01.01.2012. Die jeweils aktuellen Daten zu diesem Artikel finden Sie in unserem Produktkatalog, den Sie unter www.wago.com einsehen können. As of: 01/01/2012. Please find the newest data for this article in our product catalogue, which can be viewed under www.wago.com.

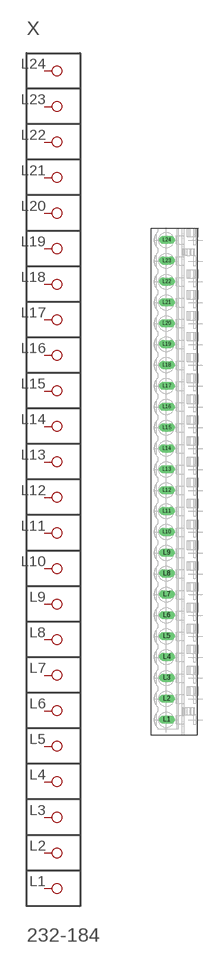
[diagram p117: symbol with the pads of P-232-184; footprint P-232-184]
Designator prefix X

## 232-184  [P-232-184]
L1  P1
L2  P2
L3  P3
L4  P4
L5  P5
L6  P6
L7  P7
L8  P8
L9  P9
L10  P10
L11  P11
L12  P12
L13  P13
L14  P14
L15  P15
L16  P16
L17  P17
L18  P18
L19  P19
L20  P20
L21  P21
L22  P22
L23  P23
L24  P24

## Footprint P-232-184 (pad centres in mm)
drill 1.3 long: L1 -2.374,-58.014; L2 -2.374,-52.934; L3 -2.374,-47.854; L4 -2.374,-42.774; L5 -2.374,-37.694; L6 -2.374,-32.614; L7 -2.374,-27.534; L8 -2.374,-22.454; L9 -2.374,-17.374; L10 -2.374,-12.294; L11 -2.374,-7.214; L12 -2.374,-2.134; L13 -2.374,2.946; L14 -2.374,8.026; L15 -2.374,13.106; L16 -2.374,18.186; L17 -2.374,23.266; L18 -2.374,28.346; L19 -2.374,33.426; L20 -2.374,38.506; L21 -2.374,43.586; L22 -2.374,48.666; L23 -2.374,53.746; L24 -2.374,58.826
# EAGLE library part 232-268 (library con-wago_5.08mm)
Serie 232, Federleiste mit abgewinkelten Einlötstiften / Series 232, Female connector with angled solder pins Polzahl / Pole No.: 8 Rastermaß / Pitch: 5.08 mm Bemessungsspannung / Rated Voltage: 160 V Nennstrom / Nominal Current: 6 A Lötstiftlänge: / Solder Pin Length: 5 mm Farbe / Color: orange / orange Stand: 01.01.2012. Die jeweils aktuellen Daten zu diesem Artikel finden Sie in unserem Produktkatalog, den Sie unter www.wago.com einsehen können. As of: 01/01/2012. Please find the newest data for this article in our product catalogue, which can be viewed under www.wago.com.

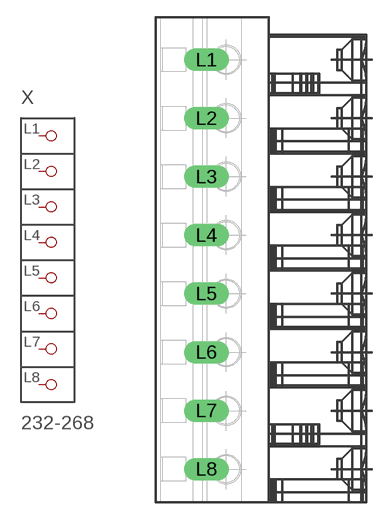
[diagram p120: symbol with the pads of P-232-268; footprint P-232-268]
Designator prefix X

## 232-268  [P-232-268]
L1  P1
L2  P2
L3  P3
L4  P4
L5  P5
L6  P6
L7  P7
L8  P8

## Footprint P-232-268 (pad centres in mm)
drill 1.3 long: L1 -4.964,17.37; L2 -4.964,12.29; L3 -4.964,7.21; L4 -4.964,2.13; L5 -4.964,-2.95; L6 -4.964,-8.03; L7 -4.964,-13.11; L8 -4.964,-18.19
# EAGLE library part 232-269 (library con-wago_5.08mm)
Serie 232, Federleiste mit abgewinkelten Einlötstiften / Series 232, Female connector with angled solder pins Polzahl / Pole No.: 9 Rastermaß / Pitch: 5.08 mm Bemessungsspannung / Rated Voltage: 160 V Nennstrom / Nominal Current: 6 A Lötstiftlänge: / Solder Pin Length: 5 mm Farbe / Color: orange / orange Stand: 01.01.2012. Die jeweils aktuellen Daten zu diesem Artikel finden Sie in unserem Produktkatalog, den Sie unter www.wago.com einsehen können. As of: 01/01/2012. Please find the newest data for this article in our product catalogue, which can be viewed under www.wago.com.

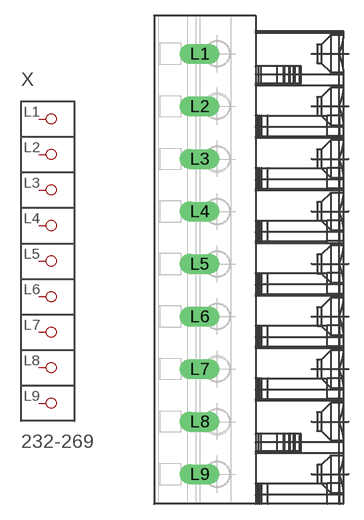
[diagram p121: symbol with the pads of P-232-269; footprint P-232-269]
Designator prefix X

## 232-269  [P-232-269]
L1  P1
L2  P2
L3  P3
L4  P4
L5  P5
L6  P6
L7  P7
L8  P8
L9  P9

## Footprint P-232-269 (pad centres in mm)
drill 1.3 long: L1 -4.987,19.91; L2 -4.987,14.83; L3 -4.987,9.75; L4 -4.987,4.67; L5 -4.987,-0.41; L6 -4.987,-5.49; L7 -4.987,-10.57; L8 -4.987,-15.65; L9 -4.987,-20.73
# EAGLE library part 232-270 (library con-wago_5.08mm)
Serie 232, Federleiste mit abgewinkelten Einlötstiften / Series 232, Female connector with angled solder pins Polzahl / Pole No.: 10 Rastermaß / Pitch: 5.08 mm Bemessungsspannung / Rated Voltage: 160 V Nennstrom / Nominal Current: 6 A Lötstiftlänge: / Solder Pin Length: 5 mm Farbe / Color: orange / orange Stand: 01.01.2012. Die jeweils aktuellen Daten zu diesem Artikel finden Sie in unserem Produktkatalog, den Sie unter www.wago.com einsehen können. As of: 01/01/2012. Please find the newest data for this article in our product catalogue, which can be viewed under www.wago.com.

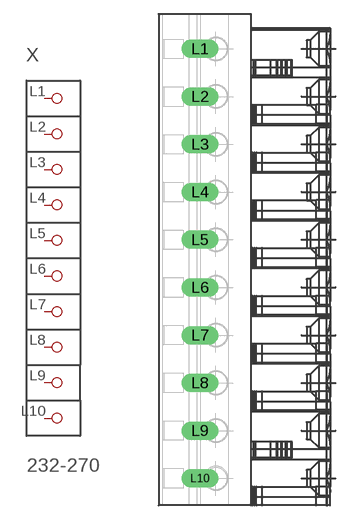
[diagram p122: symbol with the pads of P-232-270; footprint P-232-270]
Designator prefix X

## 232-270  [P-232-270]
L1  P1
L2  P2
L3  P3
L4  P4
L5  P5
L6  P6
L7  P7
L8  P8
L9  P9
L10  P10

## Footprint P-232-270 (pad centres in mm)
drill 1.3 long: L1 -5.011,22.45; L2 -5.011,17.37; L3 -5.011,12.29; L4 -5.011,7.21; L5 -5.011,2.13; L6 -5.011,-2.95; L7 -5.011,-8.03; L8 -5.011,-13.11; L9 -5.011,-18.19; L10 -5.011,-23.27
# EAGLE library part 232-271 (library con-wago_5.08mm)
Serie 232, Federleiste mit abgewinkelten Einlötstiften / Series 232, Female connector with angled solder pins Polzahl / Pole No.: 11 Rastermaß / Pitch: 5.08 mm Bemessungsspannung / Rated Voltage: 160 V Nennstrom / Nominal Current: 6 A Lötstiftlänge: / Solder Pin Length: 5 mm Farbe / Color: orange / orange Stand: 01.01.2012. Die jeweils aktuellen Daten zu diesem Artikel finden Sie in unserem Produktkatalog, den Sie unter www.wago.com einsehen können. As of: 01/01/2012. Please find the newest data for this article in our product catalogue, which can be viewed under www.wago.com.

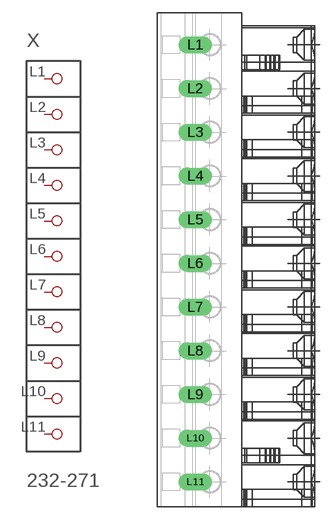
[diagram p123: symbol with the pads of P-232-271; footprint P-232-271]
Designator prefix X

## 232-271  [P-232-271]
L1  P1
L2  P2
L3  P3
L4  P4
L5  P5
L6  P6
L7  P7
L8  P8
L9  P9
L10  P10
L11  P11

## Footprint P-232-271 (pad centres in mm)
drill 1.3 long: L1 -5.035,24.99; L2 -5.035,19.91; L3 -5.035,14.83; L4 -5.035,9.75; L5 -5.035,4.67; L6 -5.035,-0.41; L7 -5.035,-5.49; L8 -5.035,-10.57; L9 -5.035,-15.65; L10 -5.035,-20.73; L11 -5.035,-25.81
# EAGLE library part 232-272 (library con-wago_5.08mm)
Serie 232, Federleiste mit abgewinkelten Einlötstiften / Series 232, Female connector with angled solder pins Polzahl / Pole No.: 12 Rastermaß / Pitch: 5.08 mm Bemessungsspannung / Rated Voltage: 160 V Nennstrom / Nominal Current: 6 A Lötstiftlänge: / Solder Pin Length: 5 mm Farbe / Color: orange / orange Stand: 01.01.2012. Die jeweils aktuellen Daten zu diesem Artikel finden Sie in unserem Produktkatalog, den Sie unter www.wago.com einsehen können. As of: 01/01/2012. Please find the newest data for this article in our product catalogue, which can be viewed under www.wago.com.

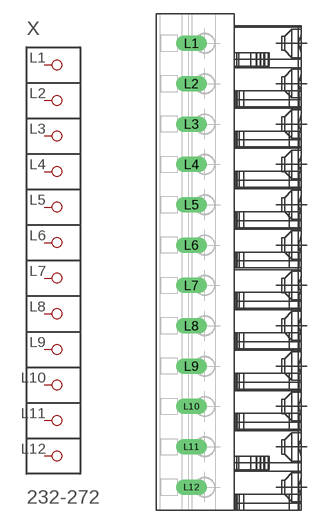
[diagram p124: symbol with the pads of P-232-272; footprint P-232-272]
Designator prefix X

## 232-272  [P-232-272]
L1  P1
L2  P2
L3  P3
L4  P4
L5  P5
L6  P6
L7  P7
L8  P8
L9  P9
L10  P10
L11  P11
L12  P12

## Footprint P-232-272 (pad centres in mm)
drill 1.3 long: L1 -5.059,27.53; L2 -5.059,22.45; L3 -5.059,17.37; L4 -5.059,12.29; L5 -5.059,7.21; L6 -5.059,2.13; L7 -5.059,-2.95; L8 -5.059,-8.03; L9 -5.059,-13.11; L10 -5.059,-18.19; L11 -5.059,-23.27; L12 -5.059,-28.35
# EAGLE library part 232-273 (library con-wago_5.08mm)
Serie 232, Federleiste mit abgewinkelten Einlötstiften / Series 232, Female connector with angled solder pins Polzahl / Pole No.: 13 Rastermaß / Pitch: 5.08 mm Bemessungsspannung / Rated Voltage: 160 V Nennstrom / Nominal Current: 6 A Lötstiftlänge: / Solder Pin Length: 5 mm Farbe / Color: orange / orange Stand: 01.01.2012. Die jeweils aktuellen Daten zu diesem Artikel finden Sie in unserem Produktkatalog, den Sie unter www.wago.com einsehen können. As of: 01/01/2012. Please find the newest data for this article in our product catalogue, which can be viewed under www.wago.com.

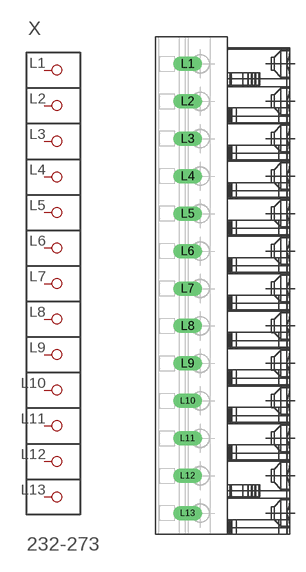
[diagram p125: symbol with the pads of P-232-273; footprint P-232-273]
Designator prefix X

## 232-273  [P-232-273]
L1  P1
L2  P2
L3  P3
L4  P4
L5  P5
L6  P6
L7  P7
L8  P8
L9  P9
L10  P10
L11  P11
L12  P12
L13  P13

## Footprint P-232-273 (pad centres in mm)
drill 1.3 long: L1 -5.083,30.07; L2 -5.083,24.99; L3 -5.083,19.91; L4 -5.083,14.83; L5 -5.083,9.75; L6 -5.083,4.67; L7 -5.083,-0.41; L8 -5.083,-5.49; L9 -5.083,-10.57; L10 -5.083,-15.65; L11 -5.083,-20.73; L12 -5.083,-25.81; L13 -5.083,-30.89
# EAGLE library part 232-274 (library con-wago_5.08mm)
Serie 232, Federleiste mit abgewinkelten Einlötstiften / Series 232, Female connector with angled solder pins Polzahl / Pole No.: 14 Rastermaß / Pitch: 5.08 mm Bemessungsspannung / Rated Voltage: 160 V Nennstrom / Nominal Current: 6 A Lötstiftlänge: / Solder Pin Length: 5 mm Farbe / Color: orange / orange Stand: 01.01.2012. Die jeweils aktuellen Daten zu diesem Artikel finden Sie in unserem Produktkatalog, den Sie unter www.wago.com einsehen können. As of: 01/01/2012. Please find the newest data for this article in our product catalogue, which can be viewed under www.wago.com.

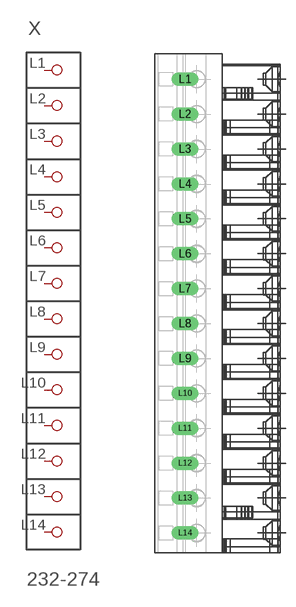
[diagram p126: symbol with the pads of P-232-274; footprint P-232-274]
Designator prefix X

## 232-274  [P-232-274]
L1  P1
L2  P2
L3  P3
L4  P4
L5  P5
L6  P6
L7  P7
L8  P8
L9  P9
L10  P10
L11  P11
L12  P12
L13  P13
L14  P14

## Footprint P-232-274 (pad centres in mm)
drill 1.3 long: L1 -5.107,32.61; L2 -5.107,27.53; L3 -5.107,22.45; L4 -5.107,17.37; L5 -5.107,12.29; L6 -5.107,7.21; L7 -5.107,2.13; L8 -5.107,-2.95; L9 -5.107,-8.03; L10 -5.107,-13.11; L11 -5.107,-18.19; L12 -5.107,-23.27; L13 -5.107,-28.35; L14 -5.107,-33.43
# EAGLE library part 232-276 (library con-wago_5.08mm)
Serie 232, Federleiste mit abgewinkelten Einlötstiften / Series 232, Female connector with angled solder pins Polzahl / Pole No.: 16 Rastermaß / Pitch: 5.08 mm Bemessungsspannung / Rated Voltage: 160 V Nennstrom / Nominal Current: 6 A Lötstiftlänge: / Solder Pin Length: 5 mm Farbe / Color: orange / orange Stand: 01.01.2012. Die jeweils aktuellen Daten zu diesem Artikel finden Sie in unserem Produktkatalog, den Sie unter www.wago.com einsehen können. As of: 01/01/2012. Please find the newest data for this article in our product catalogue, which can be viewed under www.wago.com.

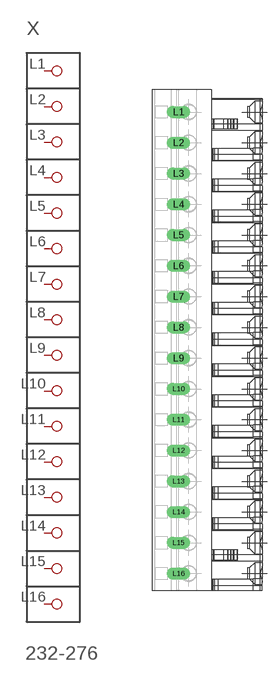
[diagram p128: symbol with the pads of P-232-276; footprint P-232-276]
Designator prefix X

## 232-276  [P-232-276]
L1  P1
L2  P2
L3  P3
L4  P4
L5  P5
L6  P6
L7  P7
L8  P8
L9  P9
L10  P10
L11  P11
L12  P12
L13  P13
L14  P14
L15  P15
L16  P16

## Footprint P-232-276 (pad centres in mm)
drill 1.3 long: L1 -5.156,37.69; L2 -5.156,32.61; L3 -5.156,27.53; L4 -5.156,22.45; L5 -5.156,17.37; L6 -5.156,12.29; L7 -5.156,7.21; L8 -5.156,2.13; L9 -5.156,-2.95; L10 -5.156,-8.03; L11 -5.156,-13.11; L12 -5.156,-18.19; L13 -5.156,-23.27; L14 -5.156,-28.35; L15 -5.156,-33.43; L16 -5.156,-38.51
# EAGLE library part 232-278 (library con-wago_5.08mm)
Serie 232, Federleiste mit abgewinkelten Einlötstiften / Series 232, Female connector with angled solder pins Polzahl / Pole No.: 18 Rastermaß / Pitch: 5.08 mm Bemessungsspannung / Rated Voltage: 160 V Nennstrom / Nominal Current: 6 A Lötstiftlänge: / Solder Pin Length: 5 mm Farbe / Color: orange / orange Stand: 01.01.2012. Die jeweils aktuellen Daten zu diesem Artikel finden Sie in unserem Produktkatalog, den Sie unter www.wago.com einsehen können. As of: 01/01/2012. Please find the newest data for this article in our product catalogue, which can be viewed under www.wago.com.

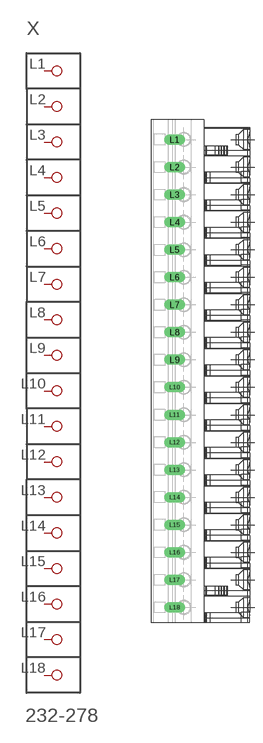
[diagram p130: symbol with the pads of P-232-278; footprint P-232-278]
Designator prefix X

## 232-278  [P-232-278]
L1  P1
L2  P2
L3  P3
L4  P4
L5  P5
L6  P6
L7  P7
L8  P8
L9  P9
L10  P10
L11  P11
L12  P12
L13  P13
L14  P14
L15  P15
L16  P16
L17  P17
L18  P18

## Footprint P-232-278 (pad centres in mm)
drill 1.3 long: L1 -5.205,42.77; L2 -5.205,37.69; L3 -5.205,32.61; L4 -5.205,27.53; L5 -5.205,22.45; L6 -5.205,17.37; L7 -5.205,12.29; L8 -5.205,7.21; L9 -5.205,2.13; L10 -5.205,-2.95; L11 -5.205,-8.03; L12 -5.205,-13.11; L13 -5.205,-18.19; L14 -5.205,-23.27; L15 -5.205,-28.35; L16 -5.205,-33.43; L17 -5.205,-38.51; L18 -5.205,-43.59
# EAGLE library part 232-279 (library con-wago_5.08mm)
Serie 232, Federleiste mit abgewinkelten Einlötstiften / Series 232, Female connector with angled solder pins Polzahl / Pole No.: 19 Rastermaß / Pitch: 5.08 mm Bemessungsspannung / Rated Voltage: 160 V Nennstrom / Nominal Current: 6 A Lötstiftlänge: / Solder Pin Length: 5 mm Farbe / Color: orange / orange Stand: 01.01.2012. Die jeweils aktuellen Daten zu diesem Artikel finden Sie in unserem Produktkatalog, den Sie unter www.wago.com einsehen können. As of: 01/01/2012. Please find the newest data for this article in our product catalogue, which can be viewed under www.wago.com.

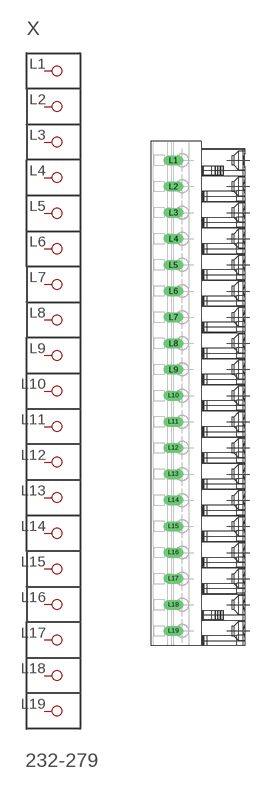
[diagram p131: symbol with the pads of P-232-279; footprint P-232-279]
Designator prefix X

## 232-279  [P-232-279]
L1  P1
L2  P2
L3  P3
L4  P4
L5  P5
L6  P6
L7  P7
L8  P8
L9  P9
L10  P10
L11  P11
L12  P12
L13  P13
L14  P14
L15  P15
L16  P16
L17  P17
L18  P18
L19  P19

## Footprint P-232-279 (pad centres in mm)
drill 1.3 long: L1 -5.23,45.31; L2 -5.23,40.23; L3 -5.23,35.15; L4 -5.23,30.07; L5 -5.23,24.99; L6 -5.23,19.91; L7 -5.23,14.83; L8 -5.23,9.75; L9 -5.23,4.67; L10 -5.23,-0.41; L11 -5.23,-5.49; L12 -5.23,-10.57; L13 -5.23,-15.65; L14 -5.23,-20.73; L15 -5.23,-25.81; L16 -5.23,-30.89; L17 -5.23,-35.97; L18 -5.23,-41.05; L19 -5.23,-46.13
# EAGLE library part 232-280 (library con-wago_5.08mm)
Serie 232, Federleiste mit abgewinkelten Einlötstiften / Series 232, Female connector with angled solder pins Polzahl / Pole No.: 20 Rastermaß / Pitch: 5.08 mm Bemessungsspannung / Rated Voltage: 160 V Nennstrom / Nominal Current: 6 A Lötstiftlänge: / Solder Pin Length: 5 mm Farbe / Color: orange / orange Stand: 01.01.2012. Die jeweils aktuellen Daten zu diesem Artikel finden Sie in unserem Produktkatalog, den Sie unter www.wago.com einsehen können. As of: 01/01/2012. Please find the newest data for this article in our product catalogue, which can be viewed under www.wago.com.

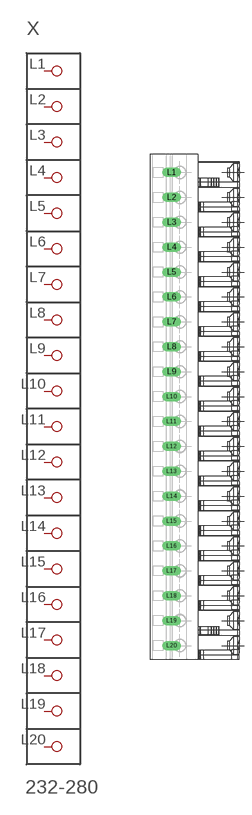
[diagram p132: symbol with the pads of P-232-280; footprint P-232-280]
Designator prefix X

## 232-280  [P-232-280]
L1  P1
L2  P2
L3  P3
L4  P4
L5  P5
L6  P6
L7  P7
L8  P8
L9  P9
L10  P10
L11  P11
L12  P12
L13  P13
L14  P14
L15  P15
L16  P16
L17  P17
L18  P18
L19  P19
L20  P20

## Footprint P-232-280 (pad centres in mm)
drill 1.3 long: L1 -5.255,47.85; L2 -5.255,42.77; L3 -5.255,37.69; L4 -5.255,32.61; L5 -5.255,27.53; L6 -5.255,22.45; L7 -5.255,17.37; L8 -5.255,12.29; L9 -5.255,7.21; L10 -5.255,2.13; L11 -5.255,-2.95; L12 -5.255,-8.03; L13 -5.255,-13.11; L14 -5.255,-18.19; L15 -5.255,-23.27; L16 -5.255,-28.35; L17 -5.255,-33.43; L18 -5.255,-38.51; L19 -5.255,-43.59; L20 -5.255,-48.67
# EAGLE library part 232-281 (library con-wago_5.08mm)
Serie 232, Federleiste mit abgewinkelten Einlötstiften / Series 232, Female connector with angled solder pins Polzahl / Pole No.: 21 Rastermaß / Pitch: 5.08 mm Bemessungsspannung / Rated Voltage: 160 V Nennstrom / Nominal Current: 6 A Lötstiftlänge: / Solder Pin Length: 5 mm Farbe / Color: orange / orange Stand: 01.01.2012. Die jeweils aktuellen Daten zu diesem Artikel finden Sie in unserem Produktkatalog, den Sie unter www.wago.com einsehen können. As of: 01/01/2012. Please find the newest data for this article in our product catalogue, which can be viewed under www.wago.com.

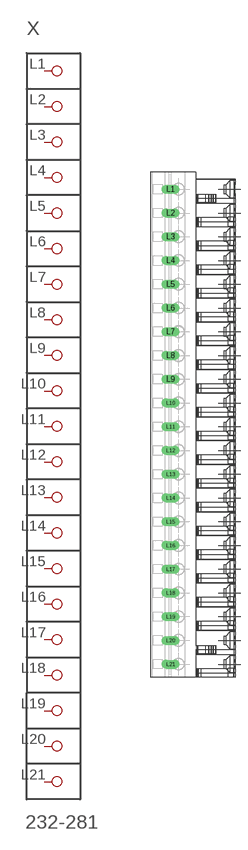
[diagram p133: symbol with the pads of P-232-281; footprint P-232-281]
Designator prefix X

## 232-281  [P-232-281]
L1  P1
L2  P2
L3  P3
L4  P4
L5  P5
L6  P6
L7  P7
L8  P8
L9  P9
L10  P10
L11  P11
L12  P12
L13  P13
L14  P14
L15  P15
L16  P16
L17  P17
L18  P18
L19  P19
L20  P20
L21  P21

## Footprint P-232-281 (pad centres in mm)
drill 1.3 long: L1 -5.28,50.39; L2 -5.28,45.31; L3 -5.28,40.23; L4 -5.28,35.15; L5 -5.28,30.07; L6 -5.28,24.99; L7 -5.28,19.91; L8 -5.28,14.83; L9 -5.28,9.75; L10 -5.28,4.67; L11 -5.28,-0.41; L12 -5.28,-5.49; L13 -5.28,-10.57; L14 -5.28,-15.65; L15 -5.28,-20.73; L16 -5.28,-25.81; L17 -5.28,-30.89; L18 -5.28,-35.97; L19 -5.28,-41.05; L20 -5.28,-46.13; L21 -5.28,-51.21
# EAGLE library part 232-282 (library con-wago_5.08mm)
Serie 232, Federleiste mit abgewinkelten Einlötstiften / Series 232, Female connector with angled solder pins Polzahl / Pole No.: 22 Rastermaß / Pitch: 5.08 mm Bemessungsspannung / Rated Voltage: 160 V Nennstrom / Nominal Current: 6 A Lötstiftlänge: / Solder Pin Length: 5 mm Farbe / Color: orange / orange Stand: 01.01.2012. Die jeweils aktuellen Daten zu diesem Artikel finden Sie in unserem Produktkatalog, den Sie unter www.wago.com einsehen können. As of: 01/01/2012. Please find the newest data for this article in our product catalogue, which can be viewed under www.wago.com.

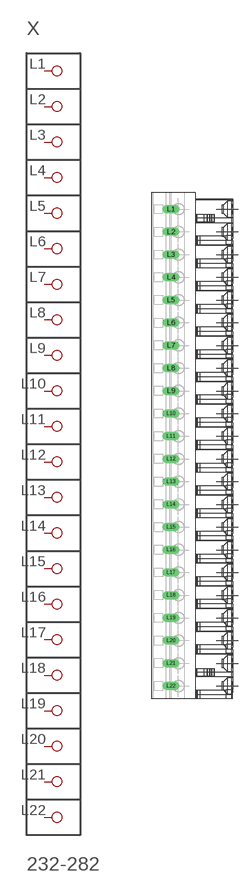
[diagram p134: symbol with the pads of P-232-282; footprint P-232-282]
Designator prefix X

## 232-282  [P-232-282]
L1  P1
L2  P2
L3  P3
L4  P4
L5  P5
L6  P6
L7  P7
L8  P8
L9  P9
L10  P10
L11  P11
L12  P12
L13  P13
L14  P14
L15  P15
L16  P16
L17  P17
L18  P18
L19  P19
L20  P20
L21  P21
L22  P22

## Footprint P-232-282 (pad centres in mm)
drill 1.3 long: L1 -5.305,52.93; L2 -5.305,47.85; L3 -5.305,42.77; L4 -5.305,37.69; L5 -5.305,32.61; L6 -5.305,27.53; L7 -5.305,22.45; L8 -5.305,17.37; L9 -5.305,12.29; L10 -5.305,7.21; L11 -5.305,2.13; L12 -5.305,-2.95; L13 -5.305,-8.03; L14 -5.305,-13.11; L15 -5.305,-18.19; L16 -5.305,-23.27; L17 -5.305,-28.35; L18 -5.305,-33.43; L19 -5.305,-38.51; L20 -5.305,-43.59; L21 -5.305,-48.67; L22 -5.305,-53.75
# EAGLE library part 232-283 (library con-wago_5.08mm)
Serie 232, Federleiste mit abgewinkelten Einlötstiften / Series 232, Female connector with angled solder pins Polzahl / Pole No.: 23 Rastermaß / Pitch: 5.08 mm Bemessungsspannung / Rated Voltage: 160 V Nennstrom / Nominal Current: 6 A Lötstiftlänge: / Solder Pin Length: 5 mm Farbe / Color: orange / orange Stand: 01.01.2012. Die jeweils aktuellen Daten zu diesem Artikel finden Sie in unserem Produktkatalog, den Sie unter www.wago.com einsehen können. As of: 01/01/2012. Please find the newest data for this article in our product catalogue, which can be viewed under www.wago.com.

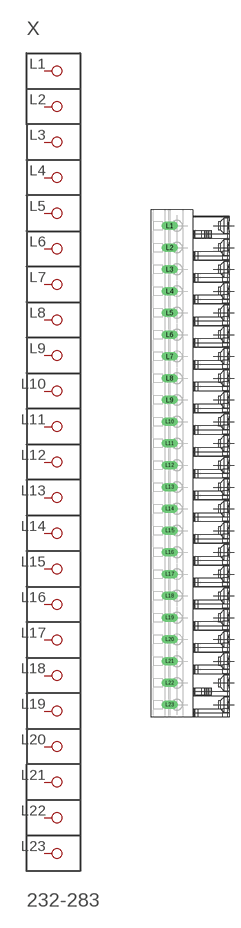
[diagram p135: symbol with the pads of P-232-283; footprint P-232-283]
Designator prefix X

## 232-283  [P-232-283]
L1  P1
L2  P2
L3  P3
L4  P4
L5  P5
L6  P6
L7  P7
L8  P8
L9  P9
L10  P10
L11  P11
L12  P12
L13  P13
L14  P14
L15  P15
L16  P16
L17  P17
L18  P18
L19  P19
L20  P20
L21  P21
L22  P22
L23  P23

## Footprint P-232-283 (pad centres in mm)
drill 1.3 long: L1 -5.33,55.47; L2 -5.33,50.39; L3 -5.33,45.31; L4 -5.33,40.23; L5 -5.33,35.15; L6 -5.33,30.07; L7 -5.33,24.99; L8 -5.33,19.91; L9 -5.33,14.83; L10 -5.33,9.75; L11 -5.33,4.67; L12 -5.33,-0.41; L13 -5.33,-5.49; L14 -5.33,-10.57; L15 -5.33,-15.65; L16 -5.33,-20.73; L17 -5.33,-25.81; L18 -5.33,-30.89; L19 -5.33,-35.97; L20 -5.33,-41.05; L21 -5.33,-46.13; L22 -5.33,-51.21; L23 -5.33,-56.29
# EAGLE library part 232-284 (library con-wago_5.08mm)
Serie 232, Federleiste mit abgewinkelten Einlötstiften / Series 232, Female connector with angled solder pins Polzahl / Pole No.: 24 Rastermaß / Pitch: 5.08 mm Bemessungsspannung / Rated Voltage: 160 V Nennstrom / Nominal Current: 6 A Lötstiftlänge: / Solder Pin Length: 5 mm Farbe / Color: orange / orange Stand: 01.01.2012. Die jeweils aktuellen Daten zu diesem Artikel finden Sie in unserem Produktkatalog, den Sie unter www.wago.com einsehen können. As of: 01/01/2012. Please find the newest data for this article in our product catalogue, which can be viewed under www.wago.com.

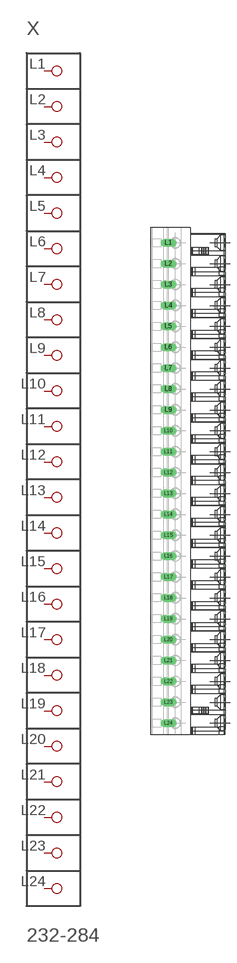
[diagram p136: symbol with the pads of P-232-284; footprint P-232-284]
Designator prefix X

## 232-284  [P-232-284]
L1  P1
L2  P2
L3  P3
L4  P4
L5  P5
L6  P6
L7  P7
L8  P8
L9  P9
L10  P10
L11  P11
L12  P12
L13  P13
L14  P14
L15  P15
L16  P16
L17  P17
L18  P18
L19  P19
L20  P20
L21  P21
L22  P22
L23  P23
L24  P24

## Footprint P-232-284 (pad centres in mm)
drill 1.3 long: L1 -5.355,58.01; L2 -5.355,52.93; L3 -5.355,47.85; L4 -5.355,42.77; L5 -5.355,37.69; L6 -5.355,32.61; L7 -5.355,27.53; L8 -5.355,22.45; L9 -5.355,17.37; L10 -5.355,12.29; L11 -5.355,7.21; L12 -5.355,2.13; L13 -5.355,-2.95; L14 -5.355,-8.03; L15 -5.355,-13.11; L16 -5.355,-18.19; L17 -5.355,-23.27; L18 -5.355,-28.35; L19 -5.355,-33.43; L20 -5.355,-38.51; L21 -5.355,-43.59; L22 -5.355,-48.67; L23 -5.355,-53.75; L24 -5.355,-58.83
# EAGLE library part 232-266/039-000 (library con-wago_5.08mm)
Serie 232, Federleiste mit abgewinkelten Einlötstiften / Series 232, Female connector with angled solder pins Polzahl / Pole No.: 6 Rastermaß / Pitch: 5.08 mm Bemessungsspannung / Rated Voltage: 160 V Nennstrom / Nominal Current: 6 A Lötstiftlänge: / Solder Pin Length: 5 mm Farbe / Color: orange / orange Stand: 01.01.2012. Die jeweils aktuellen Daten zu diesem Artikel finden Sie in unserem Produktkatalog, den Sie unter www.wago.com einsehen können. As of: 01/01/2012. Please find the newest data for this article in our product catalogue, which can be viewed under www.wago.com.

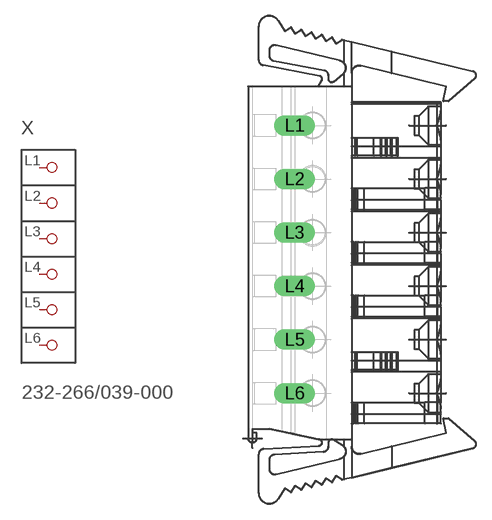
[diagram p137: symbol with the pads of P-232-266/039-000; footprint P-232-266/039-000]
Designator prefix X

## 232-266/039-000  [P-232-266/039-000]
L1  P1
L2  P2
L3  P3
L4  P4
L5  P5
L6  P6

## Footprint P-232-266/039-000 (pad centres in mm)
drill 1.3 long: L1 -6.145,12.74; L2 -6.145,7.66; L3 -6.145,2.58; L4 -6.145,-2.5; L5 -6.145,-7.58; L6 -6.145,-12.66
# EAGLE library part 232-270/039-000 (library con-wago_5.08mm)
Serie 232, Federleiste mit abgewinkelten Einlötstiften / Series 232, Female connector with angled solder pins Polzahl / Pole No.: 10 Rastermaß / Pitch: 5.08 mm Bemessungsspannung / Rated Voltage: 160 V Nennstrom / Nominal Current: 6 A Lötstiftlänge: / Solder Pin Length: 5 mm Farbe / Color: orange / orange Stand: 01.01.2012. Die jeweils aktuellen Daten zu diesem Artikel finden Sie in unserem Produktkatalog, den Sie unter www.wago.com einsehen können. As of: 01/01/2012. Please find the newest data for this article in our product catalogue, which can be viewed under www.wago.com.

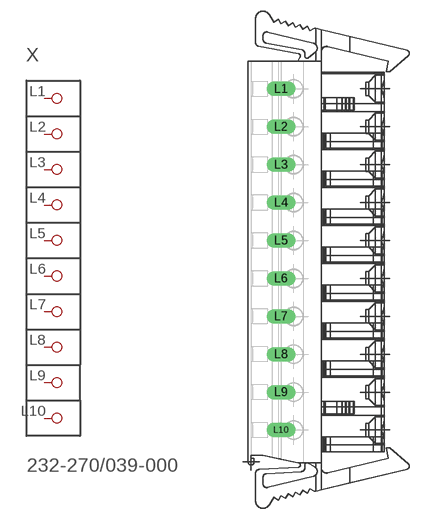
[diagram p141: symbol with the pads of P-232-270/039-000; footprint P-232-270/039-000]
Designator prefix X

## 232-270/039-000  [P-232-270/039-000]
L1  P1
L2  P2
L3  P3
L4  P4
L5  P5
L6  P6
L7  P7
L8  P8
L9  P9
L10  P10

## Footprint P-232-270/039-000 (pad centres in mm)
drill 1.3 long: L1 -6.05,22.9; L2 -6.05,17.82; L3 -6.05,12.74; L4 -6.05,7.66; L5 -6.05,2.58; L6 -6.05,-2.5; L7 -6.05,-7.58; L8 -6.05,-12.66; L9 -6.05,-17.74; L10 -6.05,-22.82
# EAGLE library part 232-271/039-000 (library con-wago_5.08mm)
Serie 232, Federleiste mit abgewinkelten Einlötstiften / Series 232, Female connector with angled solder pins Polzahl / Pole No.: 11 Rastermaß / Pitch: 5.08 mm Bemessungsspannung / Rated Voltage: 160 V Nennstrom / Nominal Current: 6 A Lötstiftlänge: / Solder Pin Length: 5 mm Farbe / Color: orange / orange Stand: 01.01.2012. Die jeweils aktuellen Daten zu diesem Artikel finden Sie in unserem Produktkatalog, den Sie unter www.wago.com einsehen können. As of: 01/01/2012. Please find the newest data for this article in our product catalogue, which can be viewed under www.wago.com.

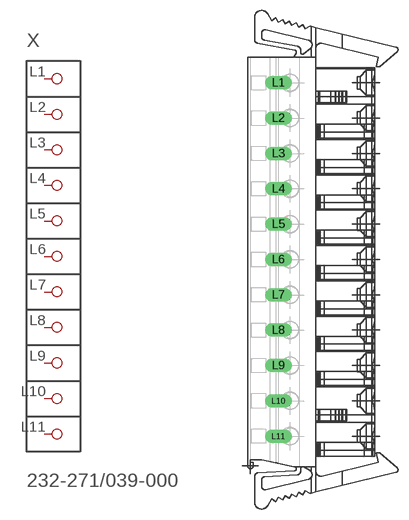
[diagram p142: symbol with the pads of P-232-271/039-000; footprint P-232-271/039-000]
Designator prefix X

## 232-271/039-000  [P-232-271/039-000]
L1  P1
L2  P2
L3  P3
L4  P4
L5  P5
L6  P6
L7  P7
L8  P8
L9  P9
L10  P10
L11  P11

## Footprint P-232-271/039-000 (pad centres in mm)
drill 1.3 long: L1 -6.026,25.44; L2 -6.026,20.36; L3 -6.026,15.28; L4 -6.026,10.2; L5 -6.026,5.12; L6 -6.026,0.04; L7 -6.026,-5.04; L8 -6.026,-10.12; L9 -6.026,-15.2; L10 -6.026,-20.28; L11 -6.026,-25.36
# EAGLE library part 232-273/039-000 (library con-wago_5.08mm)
Serie 232, Federleiste mit abgewinkelten Einlötstiften / Series 232, Female connector with angled solder pins Polzahl / Pole No.: 13 Rastermaß / Pitch: 5.08 mm Bemessungsspannung / Rated Voltage: 160 V Nennstrom / Nominal Current: 6 A Lötstiftlänge: / Solder Pin Length: 5 mm Farbe / Color: orange / orange Stand: 01.01.2012. Die jeweils aktuellen Daten zu diesem Artikel finden Sie in unserem Produktkatalog, den Sie unter www.wago.com einsehen können. As of: 01/01/2012. Please find the newest data for this article in our product catalogue, which can be viewed under www.wago.com.

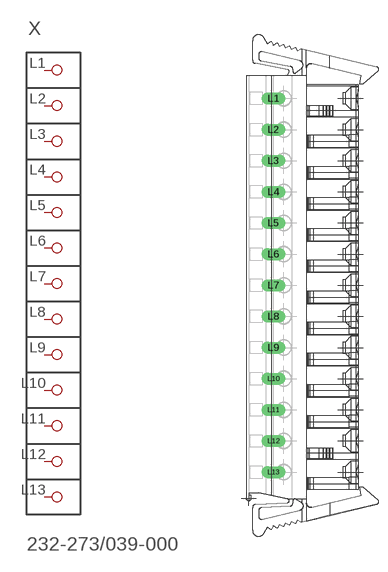
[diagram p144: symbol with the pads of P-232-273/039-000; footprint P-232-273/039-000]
Designator prefix X

## 232-273/039-000  [P-232-273/039-000]
L1  P1
L2  P2
L3  P3
L4  P4
L5  P5
L6  P6
L7  P7
L8  P8
L9  P9
L10  P10
L11  P11
L12  P12
L13  P13

## Footprint P-232-273/039-000 (pad centres in mm)
drill 1.3 long: L1 -5.977,30.52; L2 -5.977,25.44; L3 -5.977,20.36; L4 -5.977,15.28; L5 -5.977,10.2; L6 -5.977,5.12; L7 -5.977,0.04; L8 -5.977,-5.04; L9 -5.977,-10.12; L10 -5.977,-15.2; L11 -5.977,-20.28; L12 -5.977,-25.36; L13 -5.977,-30.44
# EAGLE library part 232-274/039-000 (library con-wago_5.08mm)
Serie 232, Federleiste mit abgewinkelten Einlötstiften / Series 232, Female connector with angled solder pins Polzahl / Pole No.: 14 Lötstiftlänge: / Solder Pin Length: 5 mm Farbe / Color: orange / orange Stand: 01.01.2012. Die jeweils aktuellen Daten zu diesem Artikel finden Sie in unserem Produktkatalog, den Sie unter www.wago.com einsehen können. As of: 01/01/2012. Please find the newest data for this article in our product catalogue, which can be viewed under www.wago.com.

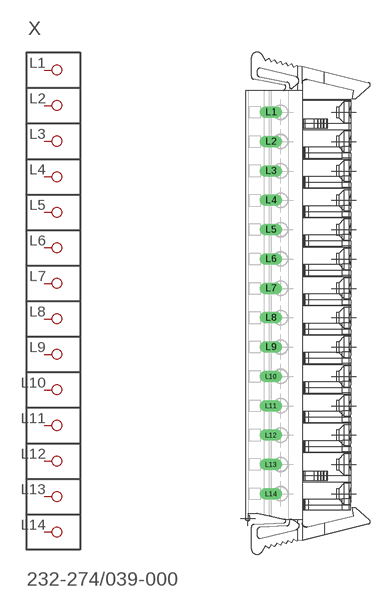
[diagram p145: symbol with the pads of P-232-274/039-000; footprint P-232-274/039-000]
Designator prefix X

## 232-274/039-000  [P-232-274/039-000]
L1  P1
L2  P2
L3  P3
L4  P4
L5  P5
L6  P6
L7  P7
L8  P8
L9  P9
L10  P10
L11  P11
L12  P12
L13  P13
L14  P14

## Footprint P-232-274/039-000 (pad centres in mm)
drill 1.3 long: L1 -5.952,33.06; L2 -5.952,27.98; L3 -5.952,22.9; L4 -5.952,17.82; L5 -5.952,12.74; L6 -5.952,7.66; L7 -5.952,2.58; L8 -5.952,-2.5; L9 -5.952,-7.58; L10 -5.952,-12.66; L11 -5.952,-17.74; L12 -5.952,-22.82; L13 -5.952,-27.9; L14 -5.952,-32.98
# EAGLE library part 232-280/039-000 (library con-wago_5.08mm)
Serie 232, Federleiste mit abgewinkelten Einlötstiften / Series 232, Female connector with angled solder pins Polzahl / Pole No.: 20 Rastermaß / Pitch: 5.08 mm Bemessungsspannung / Rated Voltage: 160 V Nennstrom / Nominal Current: 6 A Lötstiftlänge: / Solder Pin Length: 5 mm Farbe / Color: orange / orange Stand: 01.01.2012. Die jeweils aktuellen Daten zu diesem Artikel finden Sie in unserem Produktkatalog, den Sie unter www.wago.com einsehen können. As of: 01/01/2012. Please find the newest data for this article in our product catalogue, which can be viewed under www.wago.com.

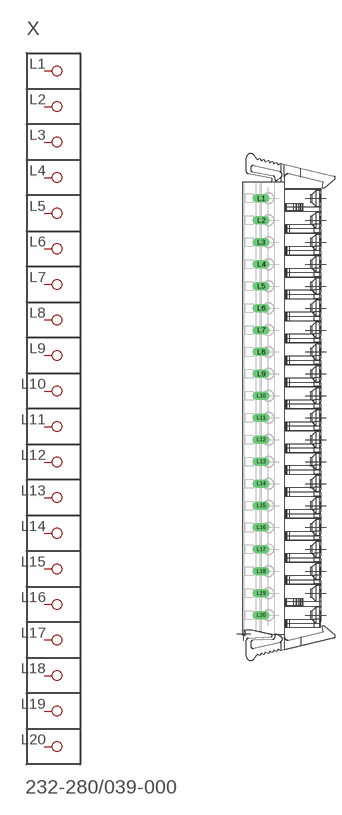
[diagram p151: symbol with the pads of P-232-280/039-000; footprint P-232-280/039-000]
Designator prefix X

## 232-280/039-000  [P-232-280/039-000]
L1  P1
L2  P2
L3  P3
L4  P4
L5  P5
L6  P6
L7  P7
L8  P8
L9  P9
L10  P10
L11  P11
L12  P12
L13  P13
L14  P14
L15  P15
L16  P16
L17  P17
L18  P18
L19  P19
L20  P20

## Footprint P-232-280/039-000 (pad centres in mm)
drill 1.3 long: L1 -5.803,48.3; L2 -5.803,43.22; L3 -5.803,38.14; L4 -5.803,33.06; L5 -5.803,27.98; L6 -5.803,22.9; L7 -5.803,17.82; L8 -5.803,12.74; L9 -5.803,7.66; L10 -5.803,2.58; L11 -5.803,-2.5; L12 -5.803,-7.58; L13 -5.803,-12.66; L14 -5.803,-17.74; L15 -5.803,-22.82; L16 -5.803,-27.9; L17 -5.803,-32.98; L18 -5.803,-38.06; L19 -5.803,-43.14; L20 -5.803,-48.22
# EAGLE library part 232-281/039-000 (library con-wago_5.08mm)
Serie 232, Federleiste mit abgewinkelten Einlötstiften / Series 232, Female connector with angled solder pins Polzahl / Pole No.: 21 Rastermaß / Pitch: 5.08 mm Bemessungsspannung / Rated Voltage: 160 V Nennstrom / Nominal Current: 6 A Lötstiftlänge: / Solder Pin Length: 5 mm Farbe / Color: orange / orange Stand: 01.01.2012. Die jeweils aktuellen Daten zu diesem Artikel finden Sie in unserem Produktkatalog, den Sie unter www.wago.com einsehen können. As of: 01/01/2012. Please find the newest data for this article in our product catalogue, which can be viewed under www.wago.com.

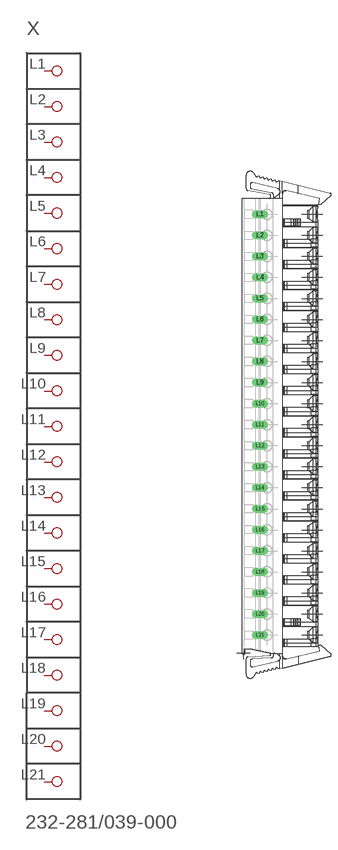
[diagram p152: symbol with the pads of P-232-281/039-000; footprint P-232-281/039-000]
Designator prefix X

## 232-281/039-000  [P-232-281/039-000]
L1  P1
L2  P2
L3  P3
L4  P4
L5  P5
L6  P6
L7  P7
L8  P8
L9  P9
L10  P10
L11  P11
L12  P12
L13  P13
L14  P14
L15  P15
L16  P16
L17  P17
L18  P18
L19  P19
L20  P20
L21  P21

## Footprint P-232-281/039-000 (pad centres in mm)
drill 1.3 long: L1 -5.778,50.84; L2 -5.778,45.76; L3 -5.778,40.68; L4 -5.778,35.6; L5 -5.778,30.52; L6 -5.778,25.44; L7 -5.778,20.36; L8 -5.778,15.28; L9 -5.778,10.2; L10 -5.778,5.12; L11 -5.778,0.04; L12 -5.778,-5.04; L13 -5.778,-10.12; L14 -5.778,-15.2; L15 -5.778,-20.28; L16 -5.778,-25.36; L17 -5.778,-30.44; L18 -5.778,-35.52; L19 -5.778,-40.6; L20 -5.778,-45.68; L21 -5.778,-50.76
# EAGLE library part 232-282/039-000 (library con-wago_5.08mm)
Serie 232, Federleiste mit abgewinkelten Einlötstiften / Series 232, Female connector with angled solder pins Polzahl / Pole No.: 22 Rastermaß / Pitch: 5.08 mm Bemessungsspannung / Rated Voltage: 160 V Nennstrom / Nominal Current: 6 A Lötstiftlänge: / Solder Pin Length: 5 mm Farbe / Color: orange / orange Stand: 01.01.2012. Die jeweils aktuellen Daten zu diesem Artikel finden Sie in unserem Produktkatalog, den Sie unter www.wago.com einsehen können. As of: 01/01/2012. Please find the newest data for this article in our product catalogue, which can be viewed under www.wago.com.

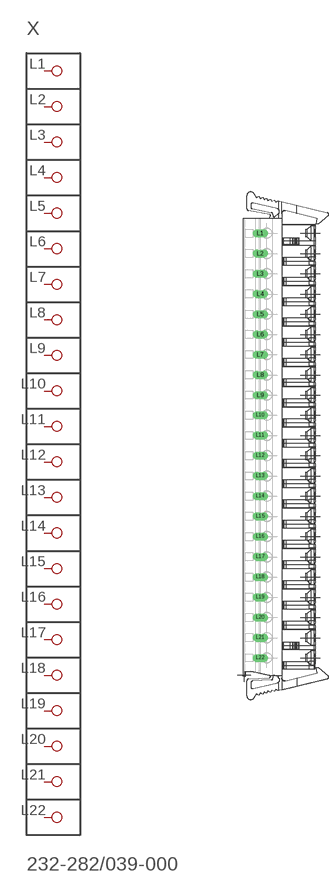
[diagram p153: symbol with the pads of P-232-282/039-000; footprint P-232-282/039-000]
Designator prefix X

## 232-282/039-000  [P-232-282/039-000]
L1  P1
L2  P2
L3  P3
L4  P4
L5  P5
L6  P6
L7  P7
L8  P8
L9  P9
L10  P10
L11  P11
L12  P12
L13  P13
L14  P14
L15  P15
L16  P16
L17  P17
L18  P18
L19  P19
L20  P20
L21  P21
L22  P22

## Footprint P-232-282/039-000 (pad centres in mm)
drill 1.3 long: L1 -5.753,53.38; L2 -5.753,48.3; L3 -5.753,43.22; L4 -5.753,38.14; L5 -5.753,33.06; L6 -5.753,27.98; L7 -5.753,22.9; L8 -5.753,17.82; L9 -5.753,12.74; L10 -5.753,7.66; L11 -5.753,2.58; L12 -5.753,-2.5; L13 -5.753,-7.58; L14 -5.753,-12.66; L15 -5.753,-17.74; L16 -5.753,-22.82; L17 -5.753,-27.9; L18 -5.753,-32.98; L19 -5.753,-38.06; L20 -5.753,-43.14; L21 -5.753,-48.22; L22 -5.753,-53.3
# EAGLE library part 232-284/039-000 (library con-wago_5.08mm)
Serie 232, Federleiste mit abgewinkelten Einlötstiften / Series 232, Female connector with angled solder pins Polzahl / Pole No.: 24 Rastermaß / Pitch: 5.08 mm Bemessungsspannung / Rated Voltage: 160 V Nennstrom / Nominal Current: 6 A Lötstiftlänge: / Solder Pin Length: 5 mm Farbe / Color: orange / orange Stand: 01.01.2012. Die jeweils aktuellen Daten zu diesem Artikel finden Sie in unserem Produktkatalog, den Sie unter www.wago.com einsehen können. As of: 01/01/2012. Please find the newest data for this article in our product catalogue, which can be viewed under www.wago.com.

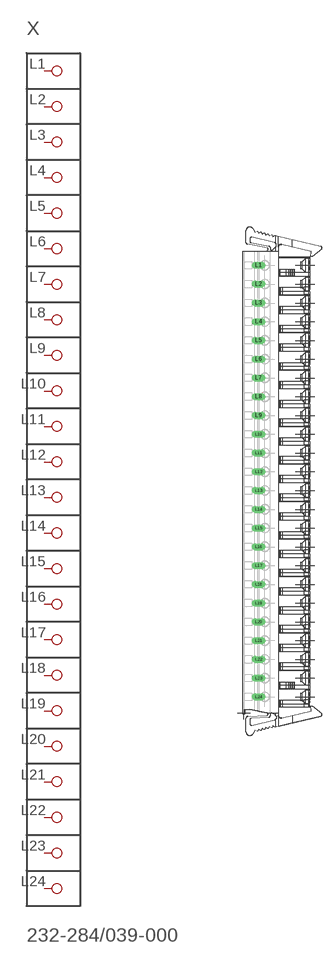
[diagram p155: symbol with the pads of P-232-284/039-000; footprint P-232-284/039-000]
Designator prefix X

## 232-284/039-000  [P-232-284/039-000]
L1  P1
L2  P2
L3  P3
L4  P4
L5  P5
L6  P6
L7  P7
L8  P8
L9  P9
L10  P10
L11  P11
L12  P12
L13  P13
L14  P14
L15  P15
L16  P16
L17  P17
L18  P18
L19  P19
L20  P20
L21  P21
L22  P22
L23  P23
L24  P24

## Footprint P-232-284/039-000 (pad centres in mm)
drill 1.3 long: L1 -5.703,58.46; L2 -5.703,53.38; L3 -5.703,48.3; L4 -5.703,43.22; L5 -5.703,38.14; L6 -5.703,33.06; L7 -5.703,27.98; L8 -5.703,22.9; L9 -5.703,17.82; L10 -5.703,12.74; L11 -5.703,7.66; L12 -5.703,2.58; L13 -5.703,-2.5; L14 -5.703,-7.58; L15 -5.703,-12.66; L16 -5.703,-17.74; L17 -5.703,-22.82; L18 -5.703,-27.9; L19 -5.703,-32.98; L20 -5.703,-38.06; L21 -5.703,-43.14; L22 -5.703,-48.22; L23 -5.703,-53.3; L24 -5.703,-58.38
